VERSION 5.7 ;
BUSBITCHARS "[]" ;
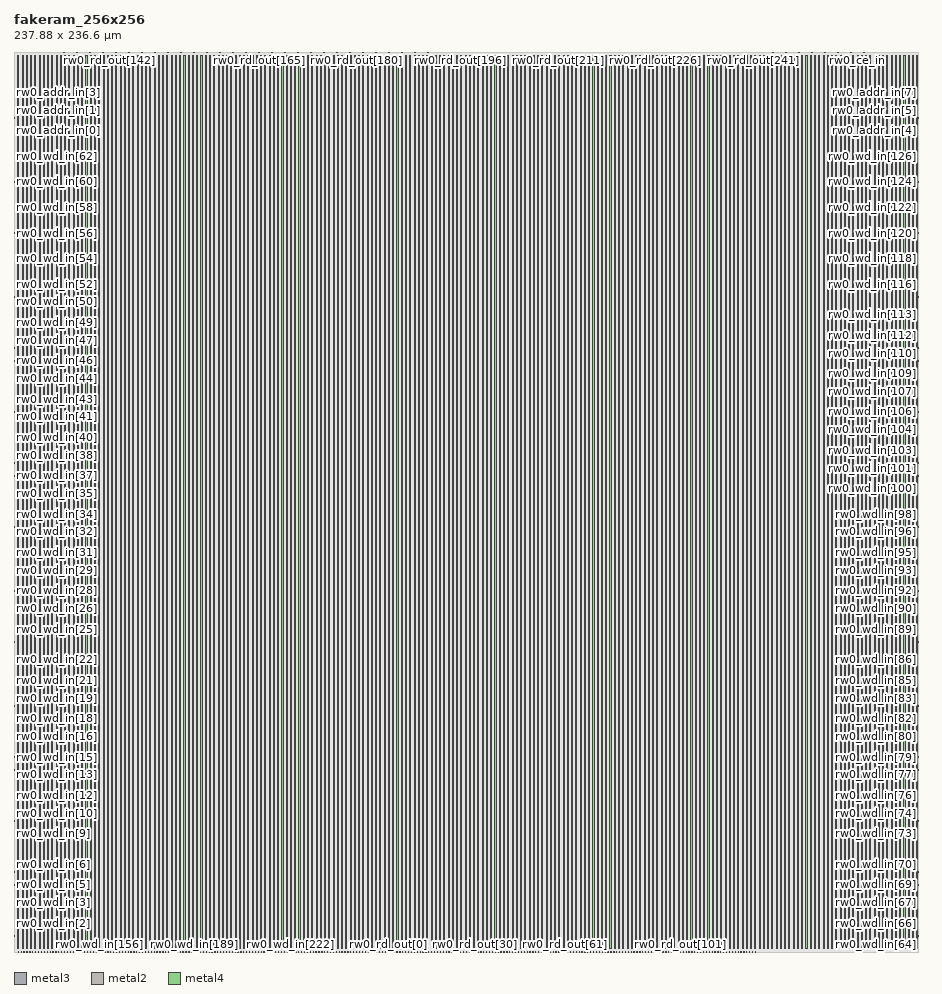
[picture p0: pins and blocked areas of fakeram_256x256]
MACRO fakeram_256x256
  FOREIGN fakeram_256x256 0 0 ;
  SYMMETRY X Y R90 ;
  SIZE 237.880 BY 236.600 ;
  CLASS BLOCK ;
  PIN rw0_wd_in[0]
    DIRECTION INPUT ;
    USE SIGNAL ;
    SHAPE ABUTMENT ;
    PORT
      LAYER metal3 ;
      RECT 0.000 0.805 0.210 0.875 ;
    END
  END rw0_wd_in[0]
  PIN rw0_wd_in[1]
    DIRECTION INPUT ;
    USE SIGNAL ;
    SHAPE ABUTMENT ;
    PORT
      LAYER metal3 ;
      RECT 0.000 4.165 0.210 4.235 ;
    END
  END rw0_wd_in[1]
  PIN rw0_wd_in[2]
    DIRECTION INPUT ;
    USE SIGNAL ;
    SHAPE ABUTMENT ;
    PORT
      LAYER metal3 ;
      RECT 0.000 7.525 0.210 7.595 ;
    END
  END rw0_wd_in[2]
  PIN rw0_wd_in[3]
    DIRECTION INPUT ;
    USE SIGNAL ;
    SHAPE ABUTMENT ;
    PORT
      LAYER metal3 ;
      RECT 0.000 10.885 0.210 10.955 ;
    END
  END rw0_wd_in[3]
  PIN rw0_wd_in[4]
    DIRECTION INPUT ;
    USE SIGNAL ;
    SHAPE ABUTMENT ;
    PORT
      LAYER metal3 ;
      RECT 0.000 14.245 0.210 14.315 ;
    END
  END rw0_wd_in[4]
  PIN rw0_wd_in[5]
    DIRECTION INPUT ;
    USE SIGNAL ;
    SHAPE ABUTMENT ;
    PORT
      LAYER metal3 ;
      RECT 0.000 17.605 0.210 17.675 ;
    END
  END rw0_wd_in[5]
  PIN rw0_wd_in[6]
    DIRECTION INPUT ;
    USE SIGNAL ;
    SHAPE ABUTMENT ;
    PORT
      LAYER metal3 ;
      RECT 0.000 20.965 0.210 21.035 ;
    END
  END rw0_wd_in[6]
  PIN rw0_wd_in[7]
    DIRECTION INPUT ;
    USE SIGNAL ;
    SHAPE ABUTMENT ;
    PORT
      LAYER metal3 ;
      RECT 0.000 24.325 0.210 24.395 ;
    END
  END rw0_wd_in[7]
  PIN rw0_wd_in[8]
    DIRECTION INPUT ;
    USE SIGNAL ;
    SHAPE ABUTMENT ;
    PORT
      LAYER metal3 ;
      RECT 0.000 27.685 0.210 27.755 ;
    END
  END rw0_wd_in[8]
  PIN rw0_wd_in[9]
    DIRECTION INPUT ;
    USE SIGNAL ;
    SHAPE ABUTMENT ;
    PORT
      LAYER metal3 ;
      RECT 0.000 31.045 0.210 31.115 ;
    END
  END rw0_wd_in[9]
  PIN rw0_wd_in[10]
    DIRECTION INPUT ;
    USE SIGNAL ;
    SHAPE ABUTMENT ;
    PORT
      LAYER metal3 ;
      RECT 0.000 34.405 0.210 34.475 ;
    END
  END rw0_wd_in[10]
  PIN rw0_wd_in[11]
    DIRECTION INPUT ;
    USE SIGNAL ;
    SHAPE ABUTMENT ;
    PORT
      LAYER metal3 ;
      RECT 0.000 37.765 0.210 37.835 ;
    END
  END rw0_wd_in[11]
  PIN rw0_wd_in[12]
    DIRECTION INPUT ;
    USE SIGNAL ;
    SHAPE ABUTMENT ;
    PORT
      LAYER metal3 ;
      RECT 0.000 41.125 0.210 41.195 ;
    END
  END rw0_wd_in[12]
  PIN rw0_wd_in[13]
    DIRECTION INPUT ;
    USE SIGNAL ;
    SHAPE ABUTMENT ;
    PORT
      LAYER metal3 ;
      RECT 0.000 44.485 0.210 44.555 ;
    END
  END rw0_wd_in[13]
  PIN rw0_wd_in[14]
    DIRECTION INPUT ;
    USE SIGNAL ;
    SHAPE ABUTMENT ;
    PORT
      LAYER metal3 ;
      RECT 0.000 47.845 0.210 47.915 ;
    END
  END rw0_wd_in[14]
  PIN rw0_wd_in[15]
    DIRECTION INPUT ;
    USE SIGNAL ;
    SHAPE ABUTMENT ;
    PORT
      LAYER metal3 ;
      RECT 0.000 51.205 0.210 51.275 ;
    END
  END rw0_wd_in[15]
  PIN rw0_wd_in[16]
    DIRECTION INPUT ;
    USE SIGNAL ;
    SHAPE ABUTMENT ;
    PORT
      LAYER metal3 ;
      RECT 0.000 54.565 0.210 54.635 ;
    END
  END rw0_wd_in[16]
  PIN rw0_wd_in[17]
    DIRECTION INPUT ;
    USE SIGNAL ;
    SHAPE ABUTMENT ;
    PORT
      LAYER metal3 ;
      RECT 0.000 57.925 0.210 57.995 ;
    END
  END rw0_wd_in[17]
  PIN rw0_wd_in[18]
    DIRECTION INPUT ;
    USE SIGNAL ;
    SHAPE ABUTMENT ;
    PORT
      LAYER metal3 ;
      RECT 0.000 61.285 0.210 61.355 ;
    END
  END rw0_wd_in[18]
  PIN rw0_wd_in[19]
    DIRECTION INPUT ;
    USE SIGNAL ;
    SHAPE ABUTMENT ;
    PORT
      LAYER metal3 ;
      RECT 0.000 64.645 0.210 64.715 ;
    END
  END rw0_wd_in[19]
  PIN rw0_wd_in[20]
    DIRECTION INPUT ;
    USE SIGNAL ;
    SHAPE ABUTMENT ;
    PORT
      LAYER metal3 ;
      RECT 0.000 68.005 0.210 68.075 ;
    END
  END rw0_wd_in[20]
  PIN rw0_wd_in[21]
    DIRECTION INPUT ;
    USE SIGNAL ;
    SHAPE ABUTMENT ;
    PORT
      LAYER metal3 ;
      RECT 0.000 71.365 0.210 71.435 ;
    END
  END rw0_wd_in[21]
  PIN rw0_wd_in[22]
    DIRECTION INPUT ;
    USE SIGNAL ;
    SHAPE ABUTMENT ;
    PORT
      LAYER metal3 ;
      RECT 0.000 74.725 0.210 74.795 ;
    END
  END rw0_wd_in[22]
  PIN rw0_wd_in[23]
    DIRECTION INPUT ;
    USE SIGNAL ;
    SHAPE ABUTMENT ;
    PORT
      LAYER metal3 ;
      RECT 0.000 78.085 0.210 78.155 ;
    END
  END rw0_wd_in[23]
  PIN rw0_wd_in[24]
    DIRECTION INPUT ;
    USE SIGNAL ;
    SHAPE ABUTMENT ;
    PORT
      LAYER metal3 ;
      RECT 0.000 81.445 0.210 81.515 ;
    END
  END rw0_wd_in[24]
  PIN rw0_wd_in[25]
    DIRECTION INPUT ;
    USE SIGNAL ;
    SHAPE ABUTMENT ;
    PORT
      LAYER metal3 ;
      RECT 0.000 84.805 0.210 84.875 ;
    END
  END rw0_wd_in[25]
  PIN rw0_wd_in[26]
    DIRECTION INPUT ;
    USE SIGNAL ;
    SHAPE ABUTMENT ;
    PORT
      LAYER metal3 ;
      RECT 0.000 88.165 0.210 88.235 ;
    END
  END rw0_wd_in[26]
  PIN rw0_wd_in[27]
    DIRECTION INPUT ;
    USE SIGNAL ;
    SHAPE ABUTMENT ;
    PORT
      LAYER metal3 ;
      RECT 0.000 91.525 0.210 91.595 ;
    END
  END rw0_wd_in[27]
  PIN rw0_wd_in[28]
    DIRECTION INPUT ;
    USE SIGNAL ;
    SHAPE ABUTMENT ;
    PORT
      LAYER metal3 ;
      RECT 0.000 94.885 0.210 94.955 ;
    END
  END rw0_wd_in[28]
  PIN rw0_wd_in[29]
    DIRECTION INPUT ;
    USE SIGNAL ;
    SHAPE ABUTMENT ;
    PORT
      LAYER metal3 ;
      RECT 0.000 98.245 0.210 98.315 ;
    END
  END rw0_wd_in[29]
  PIN rw0_wd_in[30]
    DIRECTION INPUT ;
    USE SIGNAL ;
    SHAPE ABUTMENT ;
    PORT
      LAYER metal3 ;
      RECT 0.000 101.605 0.210 101.675 ;
    END
  END rw0_wd_in[30]
  PIN rw0_wd_in[31]
    DIRECTION INPUT ;
    USE SIGNAL ;
    SHAPE ABUTMENT ;
    PORT
      LAYER metal3 ;
      RECT 0.000 104.965 0.210 105.035 ;
    END
  END rw0_wd_in[31]
  PIN rw0_wd_in[32]
    DIRECTION INPUT ;
    USE SIGNAL ;
    SHAPE ABUTMENT ;
    PORT
      LAYER metal3 ;
      RECT 0.000 108.325 0.210 108.395 ;
    END
  END rw0_wd_in[32]
  PIN rw0_wd_in[33]
    DIRECTION INPUT ;
    USE SIGNAL ;
    SHAPE ABUTMENT ;
    PORT
      LAYER metal3 ;
      RECT 0.000 111.685 0.210 111.755 ;
    END
  END rw0_wd_in[33]
  PIN rw0_wd_in[34]
    DIRECTION INPUT ;
    USE SIGNAL ;
    SHAPE ABUTMENT ;
    PORT
      LAYER metal3 ;
      RECT 0.000 115.045 0.210 115.115 ;
    END
  END rw0_wd_in[34]
  PIN rw0_wd_in[35]
    DIRECTION INPUT ;
    USE SIGNAL ;
    SHAPE ABUTMENT ;
    PORT
      LAYER metal3 ;
      RECT 0.000 118.405 0.210 118.475 ;
    END
  END rw0_wd_in[35]
  PIN rw0_wd_in[36]
    DIRECTION INPUT ;
    USE SIGNAL ;
    SHAPE ABUTMENT ;
    PORT
      LAYER metal3 ;
      RECT 0.000 121.765 0.210 121.835 ;
    END
  END rw0_wd_in[36]
  PIN rw0_wd_in[37]
    DIRECTION INPUT ;
    USE SIGNAL ;
    SHAPE ABUTMENT ;
    PORT
      LAYER metal3 ;
      RECT 0.000 125.125 0.210 125.195 ;
    END
  END rw0_wd_in[37]
  PIN rw0_wd_in[38]
    DIRECTION INPUT ;
    USE SIGNAL ;
    SHAPE ABUTMENT ;
    PORT
      LAYER metal3 ;
      RECT 0.000 128.485 0.210 128.555 ;
    END
  END rw0_wd_in[38]
  PIN rw0_wd_in[39]
    DIRECTION INPUT ;
    USE SIGNAL ;
    SHAPE ABUTMENT ;
    PORT
      LAYER metal3 ;
      RECT 0.000 131.845 0.210 131.915 ;
    END
  END rw0_wd_in[39]
  PIN rw0_wd_in[40]
    DIRECTION INPUT ;
    USE SIGNAL ;
    SHAPE ABUTMENT ;
    PORT
      LAYER metal3 ;
      RECT 0.000 135.205 0.210 135.275 ;
    END
  END rw0_wd_in[40]
  PIN rw0_wd_in[41]
    DIRECTION INPUT ;
    USE SIGNAL ;
    SHAPE ABUTMENT ;
    PORT
      LAYER metal3 ;
      RECT 0.000 138.565 0.210 138.635 ;
    END
  END rw0_wd_in[41]
  PIN rw0_wd_in[42]
    DIRECTION INPUT ;
    USE SIGNAL ;
    SHAPE ABUTMENT ;
    PORT
      LAYER metal3 ;
      RECT 0.000 141.925 0.210 141.995 ;
    END
  END rw0_wd_in[42]
  PIN rw0_wd_in[43]
    DIRECTION INPUT ;
    USE SIGNAL ;
    SHAPE ABUTMENT ;
    PORT
      LAYER metal3 ;
      RECT 0.000 145.285 0.210 145.355 ;
    END
  END rw0_wd_in[43]
  PIN rw0_wd_in[44]
    DIRECTION INPUT ;
    USE SIGNAL ;
    SHAPE ABUTMENT ;
    PORT
      LAYER metal3 ;
      RECT 0.000 148.645 0.210 148.715 ;
    END
  END rw0_wd_in[44]
  PIN rw0_wd_in[45]
    DIRECTION INPUT ;
    USE SIGNAL ;
    SHAPE ABUTMENT ;
    PORT
      LAYER metal3 ;
      RECT 0.000 152.005 0.210 152.075 ;
    END
  END rw0_wd_in[45]
  PIN rw0_wd_in[46]
    DIRECTION INPUT ;
    USE SIGNAL ;
    SHAPE ABUTMENT ;
    PORT
      LAYER metal3 ;
      RECT 0.000 155.365 0.210 155.435 ;
    END
  END rw0_wd_in[46]
  PIN rw0_wd_in[47]
    DIRECTION INPUT ;
    USE SIGNAL ;
    SHAPE ABUTMENT ;
    PORT
      LAYER metal3 ;
      RECT 0.000 158.725 0.210 158.795 ;
    END
  END rw0_wd_in[47]
  PIN rw0_wd_in[48]
    DIRECTION INPUT ;
    USE SIGNAL ;
    SHAPE ABUTMENT ;
    PORT
      LAYER metal3 ;
      RECT 0.000 162.085 0.210 162.155 ;
    END
  END rw0_wd_in[48]
  PIN rw0_wd_in[49]
    DIRECTION INPUT ;
    USE SIGNAL ;
    SHAPE ABUTMENT ;
    PORT
      LAYER metal3 ;
      RECT 0.000 165.445 0.210 165.515 ;
    END
  END rw0_wd_in[49]
  PIN rw0_wd_in[50]
    DIRECTION INPUT ;
    USE SIGNAL ;
    SHAPE ABUTMENT ;
    PORT
      LAYER metal3 ;
      RECT 0.000 168.805 0.210 168.875 ;
    END
  END rw0_wd_in[50]
  PIN rw0_wd_in[51]
    DIRECTION INPUT ;
    USE SIGNAL ;
    SHAPE ABUTMENT ;
    PORT
      LAYER metal3 ;
      RECT 0.000 172.165 0.210 172.235 ;
    END
  END rw0_wd_in[51]
  PIN rw0_wd_in[52]
    DIRECTION INPUT ;
    USE SIGNAL ;
    SHAPE ABUTMENT ;
    PORT
      LAYER metal3 ;
      RECT 0.000 175.525 0.210 175.595 ;
    END
  END rw0_wd_in[52]
  PIN rw0_wd_in[53]
    DIRECTION INPUT ;
    USE SIGNAL ;
    SHAPE ABUTMENT ;
    PORT
      LAYER metal3 ;
      RECT 0.000 178.885 0.210 178.955 ;
    END
  END rw0_wd_in[53]
  PIN rw0_wd_in[54]
    DIRECTION INPUT ;
    USE SIGNAL ;
    SHAPE ABUTMENT ;
    PORT
      LAYER metal3 ;
      RECT 0.000 182.245 0.210 182.315 ;
    END
  END rw0_wd_in[54]
  PIN rw0_wd_in[55]
    DIRECTION INPUT ;
    USE SIGNAL ;
    SHAPE ABUTMENT ;
    PORT
      LAYER metal3 ;
      RECT 0.000 185.605 0.210 185.675 ;
    END
  END rw0_wd_in[55]
  PIN rw0_wd_in[56]
    DIRECTION INPUT ;
    USE SIGNAL ;
    SHAPE ABUTMENT ;
    PORT
      LAYER metal3 ;
      RECT 0.000 188.965 0.210 189.035 ;
    END
  END rw0_wd_in[56]
  PIN rw0_wd_in[57]
    DIRECTION INPUT ;
    USE SIGNAL ;
    SHAPE ABUTMENT ;
    PORT
      LAYER metal3 ;
      RECT 0.000 192.325 0.210 192.395 ;
    END
  END rw0_wd_in[57]
  PIN rw0_wd_in[58]
    DIRECTION INPUT ;
    USE SIGNAL ;
    SHAPE ABUTMENT ;
    PORT
      LAYER metal3 ;
      RECT 0.000 195.685 0.210 195.755 ;
    END
  END rw0_wd_in[58]
  PIN rw0_wd_in[59]
    DIRECTION INPUT ;
    USE SIGNAL ;
    SHAPE ABUTMENT ;
    PORT
      LAYER metal3 ;
      RECT 0.000 199.045 0.210 199.115 ;
    END
  END rw0_wd_in[59]
  PIN rw0_wd_in[60]
    DIRECTION INPUT ;
    USE SIGNAL ;
    SHAPE ABUTMENT ;
    PORT
      LAYER metal3 ;
      RECT 0.000 202.405 0.210 202.475 ;
    END
  END rw0_wd_in[60]
  PIN rw0_wd_in[61]
    DIRECTION INPUT ;
    USE SIGNAL ;
    SHAPE ABUTMENT ;
    PORT
      LAYER metal3 ;
      RECT 0.000 205.765 0.210 205.835 ;
    END
  END rw0_wd_in[61]
  PIN rw0_wd_in[62]
    DIRECTION INPUT ;
    USE SIGNAL ;
    SHAPE ABUTMENT ;
    PORT
      LAYER metal3 ;
      RECT 0.000 209.125 0.210 209.195 ;
    END
  END rw0_wd_in[62]
  PIN rw0_wd_in[63]
    DIRECTION INPUT ;
    USE SIGNAL ;
    SHAPE ABUTMENT ;
    PORT
      LAYER metal3 ;
      RECT 0.000 212.485 0.210 212.555 ;
    END
  END rw0_wd_in[63]
  PIN rw0_wd_in[64]
    DIRECTION INPUT ;
    USE SIGNAL ;
    SHAPE ABUTMENT ;
    PORT
      LAYER metal3 ;
      RECT 237.670 0.805 237.880 0.875 ;
    END
  END rw0_wd_in[64]
  PIN rw0_wd_in[65]
    DIRECTION INPUT ;
    USE SIGNAL ;
    SHAPE ABUTMENT ;
    PORT
      LAYER metal3 ;
      RECT 237.670 4.165 237.880 4.235 ;
    END
  END rw0_wd_in[65]
  PIN rw0_wd_in[66]
    DIRECTION INPUT ;
    USE SIGNAL ;
    SHAPE ABUTMENT ;
    PORT
      LAYER metal3 ;
      RECT 237.670 7.525 237.880 7.595 ;
    END
  END rw0_wd_in[66]
  PIN rw0_wd_in[67]
    DIRECTION INPUT ;
    USE SIGNAL ;
    SHAPE ABUTMENT ;
    PORT
      LAYER metal3 ;
      RECT 237.670 10.885 237.880 10.955 ;
    END
  END rw0_wd_in[67]
  PIN rw0_wd_in[68]
    DIRECTION INPUT ;
    USE SIGNAL ;
    SHAPE ABUTMENT ;
    PORT
      LAYER metal3 ;
      RECT 237.670 14.245 237.880 14.315 ;
    END
  END rw0_wd_in[68]
  PIN rw0_wd_in[69]
    DIRECTION INPUT ;
    USE SIGNAL ;
    SHAPE ABUTMENT ;
    PORT
      LAYER metal3 ;
      RECT 237.670 17.605 237.880 17.675 ;
    END
  END rw0_wd_in[69]
  PIN rw0_wd_in[70]
    DIRECTION INPUT ;
    USE SIGNAL ;
    SHAPE ABUTMENT ;
    PORT
      LAYER metal3 ;
      RECT 237.670 20.965 237.880 21.035 ;
    END
  END rw0_wd_in[70]
  PIN rw0_wd_in[71]
    DIRECTION INPUT ;
    USE SIGNAL ;
    SHAPE ABUTMENT ;
    PORT
      LAYER metal3 ;
      RECT 237.670 24.325 237.880 24.395 ;
    END
  END rw0_wd_in[71]
  PIN rw0_wd_in[72]
    DIRECTION INPUT ;
    USE SIGNAL ;
    SHAPE ABUTMENT ;
    PORT
      LAYER metal3 ;
      RECT 237.670 27.685 237.880 27.755 ;
    END
  END rw0_wd_in[72]
  PIN rw0_wd_in[73]
    DIRECTION INPUT ;
    USE SIGNAL ;
    SHAPE ABUTMENT ;
    PORT
      LAYER metal3 ;
      RECT 237.670 31.045 237.880 31.115 ;
    END
  END rw0_wd_in[73]
  PIN rw0_wd_in[74]
    DIRECTION INPUT ;
    USE SIGNAL ;
    SHAPE ABUTMENT ;
    PORT
      LAYER metal3 ;
      RECT 237.670 34.405 237.880 34.475 ;
    END
  END rw0_wd_in[74]
  PIN rw0_wd_in[75]
    DIRECTION INPUT ;
    USE SIGNAL ;
    SHAPE ABUTMENT ;
    PORT
      LAYER metal3 ;
      RECT 237.670 37.765 237.880 37.835 ;
    END
  END rw0_wd_in[75]
  PIN rw0_wd_in[76]
    DIRECTION INPUT ;
    USE SIGNAL ;
    SHAPE ABUTMENT ;
    PORT
      LAYER metal3 ;
      RECT 237.670 41.125 237.880 41.195 ;
    END
  END rw0_wd_in[76]
  PIN rw0_wd_in[77]
    DIRECTION INPUT ;
    USE SIGNAL ;
    SHAPE ABUTMENT ;
    PORT
      LAYER metal3 ;
      RECT 237.670 44.485 237.880 44.555 ;
    END
  END rw0_wd_in[77]
  PIN rw0_wd_in[78]
    DIRECTION INPUT ;
    USE SIGNAL ;
    SHAPE ABUTMENT ;
    PORT
      LAYER metal3 ;
      RECT 237.670 47.845 237.880 47.915 ;
    END
  END rw0_wd_in[78]
  PIN rw0_wd_in[79]
    DIRECTION INPUT ;
    USE SIGNAL ;
    SHAPE ABUTMENT ;
    PORT
      LAYER metal3 ;
      RECT 237.670 51.205 237.880 51.275 ;
    END
  END rw0_wd_in[79]
  PIN rw0_wd_in[80]
    DIRECTION INPUT ;
    USE SIGNAL ;
    SHAPE ABUTMENT ;
    PORT
      LAYER metal3 ;
      RECT 237.670 54.565 237.880 54.635 ;
    END
  END rw0_wd_in[80]
  PIN rw0_wd_in[81]
    DIRECTION INPUT ;
    USE SIGNAL ;
    SHAPE ABUTMENT ;
    PORT
      LAYER metal3 ;
      RECT 237.670 57.925 237.880 57.995 ;
    END
  END rw0_wd_in[81]
  PIN rw0_wd_in[82]
    DIRECTION INPUT ;
    USE SIGNAL ;
    SHAPE ABUTMENT ;
    PORT
      LAYER metal3 ;
      RECT 237.670 61.285 237.880 61.355 ;
    END
  END rw0_wd_in[82]
  PIN rw0_wd_in[83]
    DIRECTION INPUT ;
    USE SIGNAL ;
    SHAPE ABUTMENT ;
    PORT
      LAYER metal3 ;
      RECT 237.670 64.645 237.880 64.715 ;
    END
  END rw0_wd_in[83]
  PIN rw0_wd_in[84]
    DIRECTION INPUT ;
    USE SIGNAL ;
    SHAPE ABUTMENT ;
    PORT
      LAYER metal3 ;
      RECT 237.670 68.005 237.880 68.075 ;
    END
  END rw0_wd_in[84]
  PIN rw0_wd_in[85]
    DIRECTION INPUT ;
    USE SIGNAL ;
    SHAPE ABUTMENT ;
    PORT
      LAYER metal3 ;
      RECT 237.670 71.365 237.880 71.435 ;
    END
  END rw0_wd_in[85]
  PIN rw0_wd_in[86]
    DIRECTION INPUT ;
    USE SIGNAL ;
    SHAPE ABUTMENT ;
    PORT
      LAYER metal3 ;
      RECT 237.670 74.725 237.880 74.795 ;
    END
  END rw0_wd_in[86]
  PIN rw0_wd_in[87]
    DIRECTION INPUT ;
    USE SIGNAL ;
    SHAPE ABUTMENT ;
    PORT
      LAYER metal3 ;
      RECT 237.670 78.085 237.880 78.155 ;
    END
  END rw0_wd_in[87]
  PIN rw0_wd_in[88]
    DIRECTION INPUT ;
    USE SIGNAL ;
    SHAPE ABUTMENT ;
    PORT
      LAYER metal3 ;
      RECT 237.670 81.445 237.880 81.515 ;
    END
  END rw0_wd_in[88]
  PIN rw0_wd_in[89]
    DIRECTION INPUT ;
    USE SIGNAL ;
    SHAPE ABUTMENT ;
    PORT
      LAYER metal3 ;
      RECT 237.670 84.805 237.880 84.875 ;
    END
  END rw0_wd_in[89]
  PIN rw0_wd_in[90]
    DIRECTION INPUT ;
    USE SIGNAL ;
    SHAPE ABUTMENT ;
    PORT
      LAYER metal3 ;
      RECT 237.670 88.165 237.880 88.235 ;
    END
  END rw0_wd_in[90]
  PIN rw0_wd_in[91]
    DIRECTION INPUT ;
    USE SIGNAL ;
    SHAPE ABUTMENT ;
    PORT
      LAYER metal3 ;
      RECT 237.670 91.525 237.880 91.595 ;
    END
  END rw0_wd_in[91]
  PIN rw0_wd_in[92]
    DIRECTION INPUT ;
    USE SIGNAL ;
    SHAPE ABUTMENT ;
    PORT
      LAYER metal3 ;
      RECT 237.670 94.885 237.880 94.955 ;
    END
  END rw0_wd_in[92]
  PIN rw0_wd_in[93]
    DIRECTION INPUT ;
    USE SIGNAL ;
    SHAPE ABUTMENT ;
    PORT
      LAYER metal3 ;
      RECT 237.670 98.245 237.880 98.315 ;
    END
  END rw0_wd_in[93]
  PIN rw0_wd_in[94]
    DIRECTION INPUT ;
    USE SIGNAL ;
    SHAPE ABUTMENT ;
    PORT
      LAYER metal3 ;
      RECT 237.670 101.605 237.880 101.675 ;
    END
  END rw0_wd_in[94]
  PIN rw0_wd_in[95]
    DIRECTION INPUT ;
    USE SIGNAL ;
    SHAPE ABUTMENT ;
    PORT
      LAYER metal3 ;
      RECT 237.670 104.965 237.880 105.035 ;
    END
  END rw0_wd_in[95]
  PIN rw0_wd_in[96]
    DIRECTION INPUT ;
    USE SIGNAL ;
    SHAPE ABUTMENT ;
    PORT
      LAYER metal3 ;
      RECT 237.670 108.325 237.880 108.395 ;
    END
  END rw0_wd_in[96]
  PIN rw0_wd_in[97]
    DIRECTION INPUT ;
    USE SIGNAL ;
    SHAPE ABUTMENT ;
    PORT
      LAYER metal3 ;
      RECT 237.670 111.685 237.880 111.755 ;
    END
  END rw0_wd_in[97]
  PIN rw0_wd_in[98]
    DIRECTION INPUT ;
    USE SIGNAL ;
    SHAPE ABUTMENT ;
    PORT
      LAYER metal3 ;
      RECT 237.670 115.045 237.880 115.115 ;
    END
  END rw0_wd_in[98]
  PIN rw0_wd_in[99]
    DIRECTION INPUT ;
    USE SIGNAL ;
    SHAPE ABUTMENT ;
    PORT
      LAYER metal3 ;
      RECT 237.670 118.405 237.880 118.475 ;
    END
  END rw0_wd_in[99]
  PIN rw0_wd_in[100]
    DIRECTION INPUT ;
    USE SIGNAL ;
    SHAPE ABUTMENT ;
    PORT
      LAYER metal3 ;
      RECT 237.670 121.765 237.880 121.835 ;
    END
  END rw0_wd_in[100]
  PIN rw0_wd_in[101]
    DIRECTION INPUT ;
    USE SIGNAL ;
    SHAPE ABUTMENT ;
    PORT
      LAYER metal3 ;
      RECT 237.670 125.125 237.880 125.195 ;
    END
  END rw0_wd_in[101]
  PIN rw0_wd_in[102]
    DIRECTION INPUT ;
    USE SIGNAL ;
    SHAPE ABUTMENT ;
    PORT
      LAYER metal3 ;
      RECT 237.670 128.485 237.880 128.555 ;
    END
  END rw0_wd_in[102]
  PIN rw0_wd_in[103]
    DIRECTION INPUT ;
    USE SIGNAL ;
    SHAPE ABUTMENT ;
    PORT
      LAYER metal3 ;
      RECT 237.670 131.845 237.880 131.915 ;
    END
  END rw0_wd_in[103]
  PIN rw0_wd_in[104]
    DIRECTION INPUT ;
    USE SIGNAL ;
    SHAPE ABUTMENT ;
    PORT
      LAYER metal3 ;
      RECT 237.670 135.205 237.880 135.275 ;
    END
  END rw0_wd_in[104]
  PIN rw0_wd_in[105]
    DIRECTION INPUT ;
    USE SIGNAL ;
    SHAPE ABUTMENT ;
    PORT
      LAYER metal3 ;
      RECT 237.670 138.565 237.880 138.635 ;
    END
  END rw0_wd_in[105]
  PIN rw0_wd_in[106]
    DIRECTION INPUT ;
    USE SIGNAL ;
    SHAPE ABUTMENT ;
    PORT
      LAYER metal3 ;
      RECT 237.670 141.925 237.880 141.995 ;
    END
  END rw0_wd_in[106]
  PIN rw0_wd_in[107]
    DIRECTION INPUT ;
    USE SIGNAL ;
    SHAPE ABUTMENT ;
    PORT
      LAYER metal3 ;
      RECT 237.670 145.285 237.880 145.355 ;
    END
  END rw0_wd_in[107]
  PIN rw0_wd_in[108]
    DIRECTION INPUT ;
    USE SIGNAL ;
    SHAPE ABUTMENT ;
    PORT
      LAYER metal3 ;
      RECT 237.670 148.645 237.880 148.715 ;
    END
  END rw0_wd_in[108]
  PIN rw0_wd_in[109]
    DIRECTION INPUT ;
    USE SIGNAL ;
    SHAPE ABUTMENT ;
    PORT
      LAYER metal3 ;
      RECT 237.670 152.005 237.880 152.075 ;
    END
  END rw0_wd_in[109]
  PIN rw0_wd_in[110]
    DIRECTION INPUT ;
    USE SIGNAL ;
    SHAPE ABUTMENT ;
    PORT
      LAYER metal3 ;
      RECT 237.670 155.365 237.880 155.435 ;
    END
  END rw0_wd_in[110]
  PIN rw0_wd_in[111]
    DIRECTION INPUT ;
    USE SIGNAL ;
    SHAPE ABUTMENT ;
    PORT
      LAYER metal3 ;
      RECT 237.670 158.725 237.880 158.795 ;
    END
  END rw0_wd_in[111]
  PIN rw0_wd_in[112]
    DIRECTION INPUT ;
    USE SIGNAL ;
    SHAPE ABUTMENT ;
    PORT
      LAYER metal3 ;
      RECT 237.670 162.085 237.880 162.155 ;
    END
  END rw0_wd_in[112]
  PIN rw0_wd_in[113]
    DIRECTION INPUT ;
    USE SIGNAL ;
    SHAPE ABUTMENT ;
    PORT
      LAYER metal3 ;
      RECT 237.670 165.445 237.880 165.515 ;
    END
  END rw0_wd_in[113]
  PIN rw0_wd_in[114]
    DIRECTION INPUT ;
    USE SIGNAL ;
    SHAPE ABUTMENT ;
    PORT
      LAYER metal3 ;
      RECT 237.670 168.805 237.880 168.875 ;
    END
  END rw0_wd_in[114]
  PIN rw0_wd_in[115]
    DIRECTION INPUT ;
    USE SIGNAL ;
    SHAPE ABUTMENT ;
    PORT
      LAYER metal3 ;
      RECT 237.670 172.165 237.880 172.235 ;
    END
  END rw0_wd_in[115]
  PIN rw0_wd_in[116]
    DIRECTION INPUT ;
    USE SIGNAL ;
    SHAPE ABUTMENT ;
    PORT
      LAYER metal3 ;
      RECT 237.670 175.525 237.880 175.595 ;
    END
  END rw0_wd_in[116]
  PIN rw0_wd_in[117]
    DIRECTION INPUT ;
    USE SIGNAL ;
    SHAPE ABUTMENT ;
    PORT
      LAYER metal3 ;
      RECT 237.670 178.885 237.880 178.955 ;
    END
  END rw0_wd_in[117]
  PIN rw0_wd_in[118]
    DIRECTION INPUT ;
    USE SIGNAL ;
    SHAPE ABUTMENT ;
    PORT
      LAYER metal3 ;
      RECT 237.670 182.245 237.880 182.315 ;
    END
  END rw0_wd_in[118]
  PIN rw0_wd_in[119]
    DIRECTION INPUT ;
    USE SIGNAL ;
    SHAPE ABUTMENT ;
    PORT
      LAYER metal3 ;
      RECT 237.670 185.605 237.880 185.675 ;
    END
  END rw0_wd_in[119]
  PIN rw0_wd_in[120]
    DIRECTION INPUT ;
    USE SIGNAL ;
    SHAPE ABUTMENT ;
    PORT
      LAYER metal3 ;
      RECT 237.670 188.965 237.880 189.035 ;
    END
  END rw0_wd_in[120]
  PIN rw0_wd_in[121]
    DIRECTION INPUT ;
    USE SIGNAL ;
    SHAPE ABUTMENT ;
    PORT
      LAYER metal3 ;
      RECT 237.670 192.325 237.880 192.395 ;
    END
  END rw0_wd_in[121]
  PIN rw0_wd_in[122]
    DIRECTION INPUT ;
    USE SIGNAL ;
    SHAPE ABUTMENT ;
    PORT
      LAYER metal3 ;
      RECT 237.670 195.685 237.880 195.755 ;
    END
  END rw0_wd_in[122]
  PIN rw0_wd_in[123]
    DIRECTION INPUT ;
    USE SIGNAL ;
    SHAPE ABUTMENT ;
    PORT
      LAYER metal3 ;
      RECT 237.670 199.045 237.880 199.115 ;
    END
  END rw0_wd_in[123]
  PIN rw0_wd_in[124]
    DIRECTION INPUT ;
    USE SIGNAL ;
    SHAPE ABUTMENT ;
    PORT
      LAYER metal3 ;
      RECT 237.670 202.405 237.880 202.475 ;
    END
  END rw0_wd_in[124]
  PIN rw0_wd_in[125]
    DIRECTION INPUT ;
    USE SIGNAL ;
    SHAPE ABUTMENT ;
    PORT
      LAYER metal3 ;
      RECT 237.670 205.765 237.880 205.835 ;
    END
  END rw0_wd_in[125]
  PIN rw0_wd_in[126]
    DIRECTION INPUT ;
    USE SIGNAL ;
    SHAPE ABUTMENT ;
    PORT
      LAYER metal3 ;
      RECT 237.670 209.125 237.880 209.195 ;
    END
  END rw0_wd_in[126]
  PIN rw0_wd_in[127]
    DIRECTION INPUT ;
    USE SIGNAL ;
    SHAPE ABUTMENT ;
    PORT
      LAYER metal3 ;
      RECT 237.670 212.485 237.880 212.555 ;
    END
  END rw0_wd_in[127]
  PIN rw0_wd_in[128]
    DIRECTION INPUT ;
    USE SIGNAL ;
    SHAPE ABUTMENT ;
    PORT
      LAYER metal2 ;
      RECT 1.105 0.000 1.175 0.210 ;
    END
  END rw0_wd_in[128]
  PIN rw0_wd_in[129]
    DIRECTION INPUT ;
    USE SIGNAL ;
    SHAPE ABUTMENT ;
    PORT
      LAYER metal2 ;
      RECT 1.865 0.000 1.935 0.210 ;
    END
  END rw0_wd_in[129]
  PIN rw0_wd_in[130]
    DIRECTION INPUT ;
    USE SIGNAL ;
    SHAPE ABUTMENT ;
    PORT
      LAYER metal2 ;
      RECT 2.625 0.000 2.695 0.210 ;
    END
  END rw0_wd_in[130]
  PIN rw0_wd_in[131]
    DIRECTION INPUT ;
    USE SIGNAL ;
    SHAPE ABUTMENT ;
    PORT
      LAYER metal2 ;
      RECT 3.385 0.000 3.455 0.210 ;
    END
  END rw0_wd_in[131]
  PIN rw0_wd_in[132]
    DIRECTION INPUT ;
    USE SIGNAL ;
    SHAPE ABUTMENT ;
    PORT
      LAYER metal2 ;
      RECT 4.145 0.000 4.215 0.210 ;
    END
  END rw0_wd_in[132]
  PIN rw0_wd_in[133]
    DIRECTION INPUT ;
    USE SIGNAL ;
    SHAPE ABUTMENT ;
    PORT
      LAYER metal2 ;
      RECT 4.905 0.000 4.975 0.210 ;
    END
  END rw0_wd_in[133]
  PIN rw0_wd_in[134]
    DIRECTION INPUT ;
    USE SIGNAL ;
    SHAPE ABUTMENT ;
    PORT
      LAYER metal2 ;
      RECT 5.665 0.000 5.735 0.210 ;
    END
  END rw0_wd_in[134]
  PIN rw0_wd_in[135]
    DIRECTION INPUT ;
    USE SIGNAL ;
    SHAPE ABUTMENT ;
    PORT
      LAYER metal2 ;
      RECT 6.425 0.000 6.495 0.210 ;
    END
  END rw0_wd_in[135]
  PIN rw0_wd_in[136]
    DIRECTION INPUT ;
    USE SIGNAL ;
    SHAPE ABUTMENT ;
    PORT
      LAYER metal2 ;
      RECT 7.185 0.000 7.255 0.210 ;
    END
  END rw0_wd_in[136]
  PIN rw0_wd_in[137]
    DIRECTION INPUT ;
    USE SIGNAL ;
    SHAPE ABUTMENT ;
    PORT
      LAYER metal2 ;
      RECT 7.945 0.000 8.015 0.210 ;
    END
  END rw0_wd_in[137]
  PIN rw0_wd_in[138]
    DIRECTION INPUT ;
    USE SIGNAL ;
    SHAPE ABUTMENT ;
    PORT
      LAYER metal2 ;
      RECT 8.705 0.000 8.775 0.210 ;
    END
  END rw0_wd_in[138]
  PIN rw0_wd_in[139]
    DIRECTION INPUT ;
    USE SIGNAL ;
    SHAPE ABUTMENT ;
    PORT
      LAYER metal2 ;
      RECT 9.465 0.000 9.535 0.210 ;
    END
  END rw0_wd_in[139]
  PIN rw0_wd_in[140]
    DIRECTION INPUT ;
    USE SIGNAL ;
    SHAPE ABUTMENT ;
    PORT
      LAYER metal2 ;
      RECT 10.225 0.000 10.295 0.210 ;
    END
  END rw0_wd_in[140]
  PIN rw0_wd_in[141]
    DIRECTION INPUT ;
    USE SIGNAL ;
    SHAPE ABUTMENT ;
    PORT
      LAYER metal2 ;
      RECT 10.985 0.000 11.055 0.210 ;
    END
  END rw0_wd_in[141]
  PIN rw0_wd_in[142]
    DIRECTION INPUT ;
    USE SIGNAL ;
    SHAPE ABUTMENT ;
    PORT
      LAYER metal2 ;
      RECT 11.745 0.000 11.815 0.210 ;
    END
  END rw0_wd_in[142]
  PIN rw0_wd_in[143]
    DIRECTION INPUT ;
    USE SIGNAL ;
    SHAPE ABUTMENT ;
    PORT
      LAYER metal2 ;
      RECT 12.505 0.000 12.575 0.210 ;
    END
  END rw0_wd_in[143]
  PIN rw0_wd_in[144]
    DIRECTION INPUT ;
    USE SIGNAL ;
    SHAPE ABUTMENT ;
    PORT
      LAYER metal2 ;
      RECT 13.265 0.000 13.335 0.210 ;
    END
  END rw0_wd_in[144]
  PIN rw0_wd_in[145]
    DIRECTION INPUT ;
    USE SIGNAL ;
    SHAPE ABUTMENT ;
    PORT
      LAYER metal2 ;
      RECT 14.025 0.000 14.095 0.210 ;
    END
  END rw0_wd_in[145]
  PIN rw0_wd_in[146]
    DIRECTION INPUT ;
    USE SIGNAL ;
    SHAPE ABUTMENT ;
    PORT
      LAYER metal2 ;
      RECT 14.785 0.000 14.855 0.210 ;
    END
  END rw0_wd_in[146]
  PIN rw0_wd_in[147]
    DIRECTION INPUT ;
    USE SIGNAL ;
    SHAPE ABUTMENT ;
    PORT
      LAYER metal2 ;
      RECT 15.545 0.000 15.615 0.210 ;
    END
  END rw0_wd_in[147]
  PIN rw0_wd_in[148]
    DIRECTION INPUT ;
    USE SIGNAL ;
    SHAPE ABUTMENT ;
    PORT
      LAYER metal2 ;
      RECT 16.305 0.000 16.375 0.210 ;
    END
  END rw0_wd_in[148]
  PIN rw0_wd_in[149]
    DIRECTION INPUT ;
    USE SIGNAL ;
    SHAPE ABUTMENT ;
    PORT
      LAYER metal2 ;
      RECT 17.065 0.000 17.135 0.210 ;
    END
  END rw0_wd_in[149]
  PIN rw0_wd_in[150]
    DIRECTION INPUT ;
    USE SIGNAL ;
    SHAPE ABUTMENT ;
    PORT
      LAYER metal2 ;
      RECT 17.825 0.000 17.895 0.210 ;
    END
  END rw0_wd_in[150]
  PIN rw0_wd_in[151]
    DIRECTION INPUT ;
    USE SIGNAL ;
    SHAPE ABUTMENT ;
    PORT
      LAYER metal2 ;
      RECT 18.585 0.000 18.655 0.210 ;
    END
  END rw0_wd_in[151]
  PIN rw0_wd_in[152]
    DIRECTION INPUT ;
    USE SIGNAL ;
    SHAPE ABUTMENT ;
    PORT
      LAYER metal2 ;
      RECT 19.345 0.000 19.415 0.210 ;
    END
  END rw0_wd_in[152]
  PIN rw0_wd_in[153]
    DIRECTION INPUT ;
    USE SIGNAL ;
    SHAPE ABUTMENT ;
    PORT
      LAYER metal2 ;
      RECT 20.105 0.000 20.175 0.210 ;
    END
  END rw0_wd_in[153]
  PIN rw0_wd_in[154]
    DIRECTION INPUT ;
    USE SIGNAL ;
    SHAPE ABUTMENT ;
    PORT
      LAYER metal2 ;
      RECT 20.865 0.000 20.935 0.210 ;
    END
  END rw0_wd_in[154]
  PIN rw0_wd_in[155]
    DIRECTION INPUT ;
    USE SIGNAL ;
    SHAPE ABUTMENT ;
    PORT
      LAYER metal2 ;
      RECT 21.625 0.000 21.695 0.210 ;
    END
  END rw0_wd_in[155]
  PIN rw0_wd_in[156]
    DIRECTION INPUT ;
    USE SIGNAL ;
    SHAPE ABUTMENT ;
    PORT
      LAYER metal2 ;
      RECT 22.385 0.000 22.455 0.210 ;
    END
  END rw0_wd_in[156]
  PIN rw0_wd_in[157]
    DIRECTION INPUT ;
    USE SIGNAL ;
    SHAPE ABUTMENT ;
    PORT
      LAYER metal2 ;
      RECT 23.145 0.000 23.215 0.210 ;
    END
  END rw0_wd_in[157]
  PIN rw0_wd_in[158]
    DIRECTION INPUT ;
    USE SIGNAL ;
    SHAPE ABUTMENT ;
    PORT
      LAYER metal2 ;
      RECT 23.905 0.000 23.975 0.210 ;
    END
  END rw0_wd_in[158]
  PIN rw0_wd_in[159]
    DIRECTION INPUT ;
    USE SIGNAL ;
    SHAPE ABUTMENT ;
    PORT
      LAYER metal2 ;
      RECT 24.665 0.000 24.735 0.210 ;
    END
  END rw0_wd_in[159]
  PIN rw0_wd_in[160]
    DIRECTION INPUT ;
    USE SIGNAL ;
    SHAPE ABUTMENT ;
    PORT
      LAYER metal2 ;
      RECT 25.425 0.000 25.495 0.210 ;
    END
  END rw0_wd_in[160]
  PIN rw0_wd_in[161]
    DIRECTION INPUT ;
    USE SIGNAL ;
    SHAPE ABUTMENT ;
    PORT
      LAYER metal2 ;
      RECT 26.185 0.000 26.255 0.210 ;
    END
  END rw0_wd_in[161]
  PIN rw0_wd_in[162]
    DIRECTION INPUT ;
    USE SIGNAL ;
    SHAPE ABUTMENT ;
    PORT
      LAYER metal2 ;
      RECT 26.945 0.000 27.015 0.210 ;
    END
  END rw0_wd_in[162]
  PIN rw0_wd_in[163]
    DIRECTION INPUT ;
    USE SIGNAL ;
    SHAPE ABUTMENT ;
    PORT
      LAYER metal2 ;
      RECT 27.705 0.000 27.775 0.210 ;
    END
  END rw0_wd_in[163]
  PIN rw0_wd_in[164]
    DIRECTION INPUT ;
    USE SIGNAL ;
    SHAPE ABUTMENT ;
    PORT
      LAYER metal2 ;
      RECT 28.465 0.000 28.535 0.210 ;
    END
  END rw0_wd_in[164]
  PIN rw0_wd_in[165]
    DIRECTION INPUT ;
    USE SIGNAL ;
    SHAPE ABUTMENT ;
    PORT
      LAYER metal2 ;
      RECT 29.225 0.000 29.295 0.210 ;
    END
  END rw0_wd_in[165]
  PIN rw0_wd_in[166]
    DIRECTION INPUT ;
    USE SIGNAL ;
    SHAPE ABUTMENT ;
    PORT
      LAYER metal2 ;
      RECT 29.985 0.000 30.055 0.210 ;
    END
  END rw0_wd_in[166]
  PIN rw0_wd_in[167]
    DIRECTION INPUT ;
    USE SIGNAL ;
    SHAPE ABUTMENT ;
    PORT
      LAYER metal2 ;
      RECT 30.745 0.000 30.815 0.210 ;
    END
  END rw0_wd_in[167]
  PIN rw0_wd_in[168]
    DIRECTION INPUT ;
    USE SIGNAL ;
    SHAPE ABUTMENT ;
    PORT
      LAYER metal2 ;
      RECT 31.505 0.000 31.575 0.210 ;
    END
  END rw0_wd_in[168]
  PIN rw0_wd_in[169]
    DIRECTION INPUT ;
    USE SIGNAL ;
    SHAPE ABUTMENT ;
    PORT
      LAYER metal2 ;
      RECT 32.265 0.000 32.335 0.210 ;
    END
  END rw0_wd_in[169]
  PIN rw0_wd_in[170]
    DIRECTION INPUT ;
    USE SIGNAL ;
    SHAPE ABUTMENT ;
    PORT
      LAYER metal2 ;
      RECT 33.025 0.000 33.095 0.210 ;
    END
  END rw0_wd_in[170]
  PIN rw0_wd_in[171]
    DIRECTION INPUT ;
    USE SIGNAL ;
    SHAPE ABUTMENT ;
    PORT
      LAYER metal2 ;
      RECT 33.785 0.000 33.855 0.210 ;
    END
  END rw0_wd_in[171]
  PIN rw0_wd_in[172]
    DIRECTION INPUT ;
    USE SIGNAL ;
    SHAPE ABUTMENT ;
    PORT
      LAYER metal2 ;
      RECT 34.545 0.000 34.615 0.210 ;
    END
  END rw0_wd_in[172]
  PIN rw0_wd_in[173]
    DIRECTION INPUT ;
    USE SIGNAL ;
    SHAPE ABUTMENT ;
    PORT
      LAYER metal2 ;
      RECT 35.305 0.000 35.375 0.210 ;
    END
  END rw0_wd_in[173]
  PIN rw0_wd_in[174]
    DIRECTION INPUT ;
    USE SIGNAL ;
    SHAPE ABUTMENT ;
    PORT
      LAYER metal2 ;
      RECT 36.065 0.000 36.135 0.210 ;
    END
  END rw0_wd_in[174]
  PIN rw0_wd_in[175]
    DIRECTION INPUT ;
    USE SIGNAL ;
    SHAPE ABUTMENT ;
    PORT
      LAYER metal2 ;
      RECT 36.825 0.000 36.895 0.210 ;
    END
  END rw0_wd_in[175]
  PIN rw0_wd_in[176]
    DIRECTION INPUT ;
    USE SIGNAL ;
    SHAPE ABUTMENT ;
    PORT
      LAYER metal2 ;
      RECT 37.585 0.000 37.655 0.210 ;
    END
  END rw0_wd_in[176]
  PIN rw0_wd_in[177]
    DIRECTION INPUT ;
    USE SIGNAL ;
    SHAPE ABUTMENT ;
    PORT
      LAYER metal2 ;
      RECT 38.345 0.000 38.415 0.210 ;
    END
  END rw0_wd_in[177]
  PIN rw0_wd_in[178]
    DIRECTION INPUT ;
    USE SIGNAL ;
    SHAPE ABUTMENT ;
    PORT
      LAYER metal2 ;
      RECT 39.105 0.000 39.175 0.210 ;
    END
  END rw0_wd_in[178]
  PIN rw0_wd_in[179]
    DIRECTION INPUT ;
    USE SIGNAL ;
    SHAPE ABUTMENT ;
    PORT
      LAYER metal2 ;
      RECT 39.865 0.000 39.935 0.210 ;
    END
  END rw0_wd_in[179]
  PIN rw0_wd_in[180]
    DIRECTION INPUT ;
    USE SIGNAL ;
    SHAPE ABUTMENT ;
    PORT
      LAYER metal2 ;
      RECT 40.625 0.000 40.695 0.210 ;
    END
  END rw0_wd_in[180]
  PIN rw0_wd_in[181]
    DIRECTION INPUT ;
    USE SIGNAL ;
    SHAPE ABUTMENT ;
    PORT
      LAYER metal2 ;
      RECT 41.385 0.000 41.455 0.210 ;
    END
  END rw0_wd_in[181]
  PIN rw0_wd_in[182]
    DIRECTION INPUT ;
    USE SIGNAL ;
    SHAPE ABUTMENT ;
    PORT
      LAYER metal2 ;
      RECT 42.145 0.000 42.215 0.210 ;
    END
  END rw0_wd_in[182]
  PIN rw0_wd_in[183]
    DIRECTION INPUT ;
    USE SIGNAL ;
    SHAPE ABUTMENT ;
    PORT
      LAYER metal2 ;
      RECT 42.905 0.000 42.975 0.210 ;
    END
  END rw0_wd_in[183]
  PIN rw0_wd_in[184]
    DIRECTION INPUT ;
    USE SIGNAL ;
    SHAPE ABUTMENT ;
    PORT
      LAYER metal2 ;
      RECT 43.665 0.000 43.735 0.210 ;
    END
  END rw0_wd_in[184]
  PIN rw0_wd_in[185]
    DIRECTION INPUT ;
    USE SIGNAL ;
    SHAPE ABUTMENT ;
    PORT
      LAYER metal2 ;
      RECT 44.425 0.000 44.495 0.210 ;
    END
  END rw0_wd_in[185]
  PIN rw0_wd_in[186]
    DIRECTION INPUT ;
    USE SIGNAL ;
    SHAPE ABUTMENT ;
    PORT
      LAYER metal2 ;
      RECT 45.185 0.000 45.255 0.210 ;
    END
  END rw0_wd_in[186]
  PIN rw0_wd_in[187]
    DIRECTION INPUT ;
    USE SIGNAL ;
    SHAPE ABUTMENT ;
    PORT
      LAYER metal2 ;
      RECT 45.945 0.000 46.015 0.210 ;
    END
  END rw0_wd_in[187]
  PIN rw0_wd_in[188]
    DIRECTION INPUT ;
    USE SIGNAL ;
    SHAPE ABUTMENT ;
    PORT
      LAYER metal2 ;
      RECT 46.705 0.000 46.775 0.210 ;
    END
  END rw0_wd_in[188]
  PIN rw0_wd_in[189]
    DIRECTION INPUT ;
    USE SIGNAL ;
    SHAPE ABUTMENT ;
    PORT
      LAYER metal2 ;
      RECT 47.465 0.000 47.535 0.210 ;
    END
  END rw0_wd_in[189]
  PIN rw0_wd_in[190]
    DIRECTION INPUT ;
    USE SIGNAL ;
    SHAPE ABUTMENT ;
    PORT
      LAYER metal2 ;
      RECT 48.225 0.000 48.295 0.210 ;
    END
  END rw0_wd_in[190]
  PIN rw0_wd_in[191]
    DIRECTION INPUT ;
    USE SIGNAL ;
    SHAPE ABUTMENT ;
    PORT
      LAYER metal2 ;
      RECT 48.985 0.000 49.055 0.210 ;
    END
  END rw0_wd_in[191]
  PIN rw0_wd_in[192]
    DIRECTION INPUT ;
    USE SIGNAL ;
    SHAPE ABUTMENT ;
    PORT
      LAYER metal2 ;
      RECT 49.745 0.000 49.815 0.210 ;
    END
  END rw0_wd_in[192]
  PIN rw0_wd_in[193]
    DIRECTION INPUT ;
    USE SIGNAL ;
    SHAPE ABUTMENT ;
    PORT
      LAYER metal2 ;
      RECT 50.505 0.000 50.575 0.210 ;
    END
  END rw0_wd_in[193]
  PIN rw0_wd_in[194]
    DIRECTION INPUT ;
    USE SIGNAL ;
    SHAPE ABUTMENT ;
    PORT
      LAYER metal2 ;
      RECT 51.265 0.000 51.335 0.210 ;
    END
  END rw0_wd_in[194]
  PIN rw0_wd_in[195]
    DIRECTION INPUT ;
    USE SIGNAL ;
    SHAPE ABUTMENT ;
    PORT
      LAYER metal2 ;
      RECT 52.025 0.000 52.095 0.210 ;
    END
  END rw0_wd_in[195]
  PIN rw0_wd_in[196]
    DIRECTION INPUT ;
    USE SIGNAL ;
    SHAPE ABUTMENT ;
    PORT
      LAYER metal2 ;
      RECT 52.785 0.000 52.855 0.210 ;
    END
  END rw0_wd_in[196]
  PIN rw0_wd_in[197]
    DIRECTION INPUT ;
    USE SIGNAL ;
    SHAPE ABUTMENT ;
    PORT
      LAYER metal2 ;
      RECT 53.545 0.000 53.615 0.210 ;
    END
  END rw0_wd_in[197]
  PIN rw0_wd_in[198]
    DIRECTION INPUT ;
    USE SIGNAL ;
    SHAPE ABUTMENT ;
    PORT
      LAYER metal2 ;
      RECT 54.305 0.000 54.375 0.210 ;
    END
  END rw0_wd_in[198]
  PIN rw0_wd_in[199]
    DIRECTION INPUT ;
    USE SIGNAL ;
    SHAPE ABUTMENT ;
    PORT
      LAYER metal2 ;
      RECT 55.065 0.000 55.135 0.210 ;
    END
  END rw0_wd_in[199]
  PIN rw0_wd_in[200]
    DIRECTION INPUT ;
    USE SIGNAL ;
    SHAPE ABUTMENT ;
    PORT
      LAYER metal2 ;
      RECT 55.825 0.000 55.895 0.210 ;
    END
  END rw0_wd_in[200]
  PIN rw0_wd_in[201]
    DIRECTION INPUT ;
    USE SIGNAL ;
    SHAPE ABUTMENT ;
    PORT
      LAYER metal2 ;
      RECT 56.585 0.000 56.655 0.210 ;
    END
  END rw0_wd_in[201]
  PIN rw0_wd_in[202]
    DIRECTION INPUT ;
    USE SIGNAL ;
    SHAPE ABUTMENT ;
    PORT
      LAYER metal2 ;
      RECT 57.345 0.000 57.415 0.210 ;
    END
  END rw0_wd_in[202]
  PIN rw0_wd_in[203]
    DIRECTION INPUT ;
    USE SIGNAL ;
    SHAPE ABUTMENT ;
    PORT
      LAYER metal2 ;
      RECT 58.105 0.000 58.175 0.210 ;
    END
  END rw0_wd_in[203]
  PIN rw0_wd_in[204]
    DIRECTION INPUT ;
    USE SIGNAL ;
    SHAPE ABUTMENT ;
    PORT
      LAYER metal2 ;
      RECT 58.865 0.000 58.935 0.210 ;
    END
  END rw0_wd_in[204]
  PIN rw0_wd_in[205]
    DIRECTION INPUT ;
    USE SIGNAL ;
    SHAPE ABUTMENT ;
    PORT
      LAYER metal2 ;
      RECT 59.625 0.000 59.695 0.210 ;
    END
  END rw0_wd_in[205]
  PIN rw0_wd_in[206]
    DIRECTION INPUT ;
    USE SIGNAL ;
    SHAPE ABUTMENT ;
    PORT
      LAYER metal2 ;
      RECT 60.385 0.000 60.455 0.210 ;
    END
  END rw0_wd_in[206]
  PIN rw0_wd_in[207]
    DIRECTION INPUT ;
    USE SIGNAL ;
    SHAPE ABUTMENT ;
    PORT
      LAYER metal2 ;
      RECT 61.145 0.000 61.215 0.210 ;
    END
  END rw0_wd_in[207]
  PIN rw0_wd_in[208]
    DIRECTION INPUT ;
    USE SIGNAL ;
    SHAPE ABUTMENT ;
    PORT
      LAYER metal2 ;
      RECT 61.905 0.000 61.975 0.210 ;
    END
  END rw0_wd_in[208]
  PIN rw0_wd_in[209]
    DIRECTION INPUT ;
    USE SIGNAL ;
    SHAPE ABUTMENT ;
    PORT
      LAYER metal2 ;
      RECT 62.665 0.000 62.735 0.210 ;
    END
  END rw0_wd_in[209]
  PIN rw0_wd_in[210]
    DIRECTION INPUT ;
    USE SIGNAL ;
    SHAPE ABUTMENT ;
    PORT
      LAYER metal2 ;
      RECT 63.425 0.000 63.495 0.210 ;
    END
  END rw0_wd_in[210]
  PIN rw0_wd_in[211]
    DIRECTION INPUT ;
    USE SIGNAL ;
    SHAPE ABUTMENT ;
    PORT
      LAYER metal2 ;
      RECT 64.185 0.000 64.255 0.210 ;
    END
  END rw0_wd_in[211]
  PIN rw0_wd_in[212]
    DIRECTION INPUT ;
    USE SIGNAL ;
    SHAPE ABUTMENT ;
    PORT
      LAYER metal2 ;
      RECT 64.945 0.000 65.015 0.210 ;
    END
  END rw0_wd_in[212]
  PIN rw0_wd_in[213]
    DIRECTION INPUT ;
    USE SIGNAL ;
    SHAPE ABUTMENT ;
    PORT
      LAYER metal2 ;
      RECT 65.705 0.000 65.775 0.210 ;
    END
  END rw0_wd_in[213]
  PIN rw0_wd_in[214]
    DIRECTION INPUT ;
    USE SIGNAL ;
    SHAPE ABUTMENT ;
    PORT
      LAYER metal2 ;
      RECT 66.465 0.000 66.535 0.210 ;
    END
  END rw0_wd_in[214]
  PIN rw0_wd_in[215]
    DIRECTION INPUT ;
    USE SIGNAL ;
    SHAPE ABUTMENT ;
    PORT
      LAYER metal2 ;
      RECT 67.225 0.000 67.295 0.210 ;
    END
  END rw0_wd_in[215]
  PIN rw0_wd_in[216]
    DIRECTION INPUT ;
    USE SIGNAL ;
    SHAPE ABUTMENT ;
    PORT
      LAYER metal2 ;
      RECT 67.985 0.000 68.055 0.210 ;
    END
  END rw0_wd_in[216]
  PIN rw0_wd_in[217]
    DIRECTION INPUT ;
    USE SIGNAL ;
    SHAPE ABUTMENT ;
    PORT
      LAYER metal2 ;
      RECT 68.745 0.000 68.815 0.210 ;
    END
  END rw0_wd_in[217]
  PIN rw0_wd_in[218]
    DIRECTION INPUT ;
    USE SIGNAL ;
    SHAPE ABUTMENT ;
    PORT
      LAYER metal2 ;
      RECT 69.505 0.000 69.575 0.210 ;
    END
  END rw0_wd_in[218]
  PIN rw0_wd_in[219]
    DIRECTION INPUT ;
    USE SIGNAL ;
    SHAPE ABUTMENT ;
    PORT
      LAYER metal2 ;
      RECT 70.265 0.000 70.335 0.210 ;
    END
  END rw0_wd_in[219]
  PIN rw0_wd_in[220]
    DIRECTION INPUT ;
    USE SIGNAL ;
    SHAPE ABUTMENT ;
    PORT
      LAYER metal2 ;
      RECT 71.025 0.000 71.095 0.210 ;
    END
  END rw0_wd_in[220]
  PIN rw0_wd_in[221]
    DIRECTION INPUT ;
    USE SIGNAL ;
    SHAPE ABUTMENT ;
    PORT
      LAYER metal2 ;
      RECT 71.785 0.000 71.855 0.210 ;
    END
  END rw0_wd_in[221]
  PIN rw0_wd_in[222]
    DIRECTION INPUT ;
    USE SIGNAL ;
    SHAPE ABUTMENT ;
    PORT
      LAYER metal2 ;
      RECT 72.545 0.000 72.615 0.210 ;
    END
  END rw0_wd_in[222]
  PIN rw0_wd_in[223]
    DIRECTION INPUT ;
    USE SIGNAL ;
    SHAPE ABUTMENT ;
    PORT
      LAYER metal2 ;
      RECT 73.305 0.000 73.375 0.210 ;
    END
  END rw0_wd_in[223]
  PIN rw0_wd_in[224]
    DIRECTION INPUT ;
    USE SIGNAL ;
    SHAPE ABUTMENT ;
    PORT
      LAYER metal2 ;
      RECT 74.065 0.000 74.135 0.210 ;
    END
  END rw0_wd_in[224]
  PIN rw0_wd_in[225]
    DIRECTION INPUT ;
    USE SIGNAL ;
    SHAPE ABUTMENT ;
    PORT
      LAYER metal2 ;
      RECT 74.825 0.000 74.895 0.210 ;
    END
  END rw0_wd_in[225]
  PIN rw0_wd_in[226]
    DIRECTION INPUT ;
    USE SIGNAL ;
    SHAPE ABUTMENT ;
    PORT
      LAYER metal2 ;
      RECT 75.585 0.000 75.655 0.210 ;
    END
  END rw0_wd_in[226]
  PIN rw0_wd_in[227]
    DIRECTION INPUT ;
    USE SIGNAL ;
    SHAPE ABUTMENT ;
    PORT
      LAYER metal2 ;
      RECT 76.345 0.000 76.415 0.210 ;
    END
  END rw0_wd_in[227]
  PIN rw0_wd_in[228]
    DIRECTION INPUT ;
    USE SIGNAL ;
    SHAPE ABUTMENT ;
    PORT
      LAYER metal2 ;
      RECT 77.105 0.000 77.175 0.210 ;
    END
  END rw0_wd_in[228]
  PIN rw0_wd_in[229]
    DIRECTION INPUT ;
    USE SIGNAL ;
    SHAPE ABUTMENT ;
    PORT
      LAYER metal2 ;
      RECT 77.865 0.000 77.935 0.210 ;
    END
  END rw0_wd_in[229]
  PIN rw0_wd_in[230]
    DIRECTION INPUT ;
    USE SIGNAL ;
    SHAPE ABUTMENT ;
    PORT
      LAYER metal2 ;
      RECT 78.625 0.000 78.695 0.210 ;
    END
  END rw0_wd_in[230]
  PIN rw0_wd_in[231]
    DIRECTION INPUT ;
    USE SIGNAL ;
    SHAPE ABUTMENT ;
    PORT
      LAYER metal2 ;
      RECT 79.385 0.000 79.455 0.210 ;
    END
  END rw0_wd_in[231]
  PIN rw0_wd_in[232]
    DIRECTION INPUT ;
    USE SIGNAL ;
    SHAPE ABUTMENT ;
    PORT
      LAYER metal2 ;
      RECT 80.145 0.000 80.215 0.210 ;
    END
  END rw0_wd_in[232]
  PIN rw0_wd_in[233]
    DIRECTION INPUT ;
    USE SIGNAL ;
    SHAPE ABUTMENT ;
    PORT
      LAYER metal2 ;
      RECT 80.905 0.000 80.975 0.210 ;
    END
  END rw0_wd_in[233]
  PIN rw0_wd_in[234]
    DIRECTION INPUT ;
    USE SIGNAL ;
    SHAPE ABUTMENT ;
    PORT
      LAYER metal2 ;
      RECT 81.665 0.000 81.735 0.210 ;
    END
  END rw0_wd_in[234]
  PIN rw0_wd_in[235]
    DIRECTION INPUT ;
    USE SIGNAL ;
    SHAPE ABUTMENT ;
    PORT
      LAYER metal2 ;
      RECT 82.425 0.000 82.495 0.210 ;
    END
  END rw0_wd_in[235]
  PIN rw0_wd_in[236]
    DIRECTION INPUT ;
    USE SIGNAL ;
    SHAPE ABUTMENT ;
    PORT
      LAYER metal2 ;
      RECT 83.185 0.000 83.255 0.210 ;
    END
  END rw0_wd_in[236]
  PIN rw0_wd_in[237]
    DIRECTION INPUT ;
    USE SIGNAL ;
    SHAPE ABUTMENT ;
    PORT
      LAYER metal2 ;
      RECT 83.945 0.000 84.015 0.210 ;
    END
  END rw0_wd_in[237]
  PIN rw0_wd_in[238]
    DIRECTION INPUT ;
    USE SIGNAL ;
    SHAPE ABUTMENT ;
    PORT
      LAYER metal2 ;
      RECT 84.705 0.000 84.775 0.210 ;
    END
  END rw0_wd_in[238]
  PIN rw0_wd_in[239]
    DIRECTION INPUT ;
    USE SIGNAL ;
    SHAPE ABUTMENT ;
    PORT
      LAYER metal2 ;
      RECT 85.465 0.000 85.535 0.210 ;
    END
  END rw0_wd_in[239]
  PIN rw0_wd_in[240]
    DIRECTION INPUT ;
    USE SIGNAL ;
    SHAPE ABUTMENT ;
    PORT
      LAYER metal2 ;
      RECT 86.225 0.000 86.295 0.210 ;
    END
  END rw0_wd_in[240]
  PIN rw0_wd_in[241]
    DIRECTION INPUT ;
    USE SIGNAL ;
    SHAPE ABUTMENT ;
    PORT
      LAYER metal2 ;
      RECT 86.985 0.000 87.055 0.210 ;
    END
  END rw0_wd_in[241]
  PIN rw0_wd_in[242]
    DIRECTION INPUT ;
    USE SIGNAL ;
    SHAPE ABUTMENT ;
    PORT
      LAYER metal2 ;
      RECT 87.745 0.000 87.815 0.210 ;
    END
  END rw0_wd_in[242]
  PIN rw0_wd_in[243]
    DIRECTION INPUT ;
    USE SIGNAL ;
    SHAPE ABUTMENT ;
    PORT
      LAYER metal2 ;
      RECT 88.505 0.000 88.575 0.210 ;
    END
  END rw0_wd_in[243]
  PIN rw0_wd_in[244]
    DIRECTION INPUT ;
    USE SIGNAL ;
    SHAPE ABUTMENT ;
    PORT
      LAYER metal2 ;
      RECT 89.265 0.000 89.335 0.210 ;
    END
  END rw0_wd_in[244]
  PIN rw0_wd_in[245]
    DIRECTION INPUT ;
    USE SIGNAL ;
    SHAPE ABUTMENT ;
    PORT
      LAYER metal2 ;
      RECT 90.025 0.000 90.095 0.210 ;
    END
  END rw0_wd_in[245]
  PIN rw0_wd_in[246]
    DIRECTION INPUT ;
    USE SIGNAL ;
    SHAPE ABUTMENT ;
    PORT
      LAYER metal2 ;
      RECT 90.785 0.000 90.855 0.210 ;
    END
  END rw0_wd_in[246]
  PIN rw0_wd_in[247]
    DIRECTION INPUT ;
    USE SIGNAL ;
    SHAPE ABUTMENT ;
    PORT
      LAYER metal2 ;
      RECT 91.545 0.000 91.615 0.210 ;
    END
  END rw0_wd_in[247]
  PIN rw0_wd_in[248]
    DIRECTION INPUT ;
    USE SIGNAL ;
    SHAPE ABUTMENT ;
    PORT
      LAYER metal2 ;
      RECT 92.305 0.000 92.375 0.210 ;
    END
  END rw0_wd_in[248]
  PIN rw0_wd_in[249]
    DIRECTION INPUT ;
    USE SIGNAL ;
    SHAPE ABUTMENT ;
    PORT
      LAYER metal2 ;
      RECT 93.065 0.000 93.135 0.210 ;
    END
  END rw0_wd_in[249]
  PIN rw0_wd_in[250]
    DIRECTION INPUT ;
    USE SIGNAL ;
    SHAPE ABUTMENT ;
    PORT
      LAYER metal2 ;
      RECT 93.825 0.000 93.895 0.210 ;
    END
  END rw0_wd_in[250]
  PIN rw0_wd_in[251]
    DIRECTION INPUT ;
    USE SIGNAL ;
    SHAPE ABUTMENT ;
    PORT
      LAYER metal2 ;
      RECT 94.585 0.000 94.655 0.210 ;
    END
  END rw0_wd_in[251]
  PIN rw0_wd_in[252]
    DIRECTION INPUT ;
    USE SIGNAL ;
    SHAPE ABUTMENT ;
    PORT
      LAYER metal2 ;
      RECT 95.345 0.000 95.415 0.210 ;
    END
  END rw0_wd_in[252]
  PIN rw0_wd_in[253]
    DIRECTION INPUT ;
    USE SIGNAL ;
    SHAPE ABUTMENT ;
    PORT
      LAYER metal2 ;
      RECT 96.105 0.000 96.175 0.210 ;
    END
  END rw0_wd_in[253]
  PIN rw0_wd_in[254]
    DIRECTION INPUT ;
    USE SIGNAL ;
    SHAPE ABUTMENT ;
    PORT
      LAYER metal2 ;
      RECT 96.865 0.000 96.935 0.210 ;
    END
  END rw0_wd_in[254]
  PIN rw0_wd_in[255]
    DIRECTION INPUT ;
    USE SIGNAL ;
    SHAPE ABUTMENT ;
    PORT
      LAYER metal2 ;
      RECT 97.625 0.000 97.695 0.210 ;
    END
  END rw0_wd_in[255]
  PIN rw0_rd_out[0]
    DIRECTION OUTPUT ;
    USE SIGNAL ;
    SHAPE ABUTMENT ;
    PORT
      LAYER metal2 ;
      RECT 98.385 0.000 98.455 0.210 ;
    END
  END rw0_rd_out[0]
  PIN rw0_rd_out[1]
    DIRECTION OUTPUT ;
    USE SIGNAL ;
    SHAPE ABUTMENT ;
    PORT
      LAYER metal2 ;
      RECT 99.145 0.000 99.215 0.210 ;
    END
  END rw0_rd_out[1]
  PIN rw0_rd_out[2]
    DIRECTION OUTPUT ;
    USE SIGNAL ;
    SHAPE ABUTMENT ;
    PORT
      LAYER metal2 ;
      RECT 99.905 0.000 99.975 0.210 ;
    END
  END rw0_rd_out[2]
  PIN rw0_rd_out[3]
    DIRECTION OUTPUT ;
    USE SIGNAL ;
    SHAPE ABUTMENT ;
    PORT
      LAYER metal2 ;
      RECT 100.665 0.000 100.735 0.210 ;
    END
  END rw0_rd_out[3]
  PIN rw0_rd_out[4]
    DIRECTION OUTPUT ;
    USE SIGNAL ;
    SHAPE ABUTMENT ;
    PORT
      LAYER metal2 ;
      RECT 101.425 0.000 101.495 0.210 ;
    END
  END rw0_rd_out[4]
  PIN rw0_rd_out[5]
    DIRECTION OUTPUT ;
    USE SIGNAL ;
    SHAPE ABUTMENT ;
    PORT
      LAYER metal2 ;
      RECT 102.185 0.000 102.255 0.210 ;
    END
  END rw0_rd_out[5]
  PIN rw0_rd_out[6]
    DIRECTION OUTPUT ;
    USE SIGNAL ;
    SHAPE ABUTMENT ;
    PORT
      LAYER metal2 ;
      RECT 102.945 0.000 103.015 0.210 ;
    END
  END rw0_rd_out[6]
  PIN rw0_rd_out[7]
    DIRECTION OUTPUT ;
    USE SIGNAL ;
    SHAPE ABUTMENT ;
    PORT
      LAYER metal2 ;
      RECT 103.705 0.000 103.775 0.210 ;
    END
  END rw0_rd_out[7]
  PIN rw0_rd_out[8]
    DIRECTION OUTPUT ;
    USE SIGNAL ;
    SHAPE ABUTMENT ;
    PORT
      LAYER metal2 ;
      RECT 104.465 0.000 104.535 0.210 ;
    END
  END rw0_rd_out[8]
  PIN rw0_rd_out[9]
    DIRECTION OUTPUT ;
    USE SIGNAL ;
    SHAPE ABUTMENT ;
    PORT
      LAYER metal2 ;
      RECT 105.225 0.000 105.295 0.210 ;
    END
  END rw0_rd_out[9]
  PIN rw0_rd_out[10]
    DIRECTION OUTPUT ;
    USE SIGNAL ;
    SHAPE ABUTMENT ;
    PORT
      LAYER metal2 ;
      RECT 105.985 0.000 106.055 0.210 ;
    END
  END rw0_rd_out[10]
  PIN rw0_rd_out[11]
    DIRECTION OUTPUT ;
    USE SIGNAL ;
    SHAPE ABUTMENT ;
    PORT
      LAYER metal2 ;
      RECT 106.745 0.000 106.815 0.210 ;
    END
  END rw0_rd_out[11]
  PIN rw0_rd_out[12]
    DIRECTION OUTPUT ;
    USE SIGNAL ;
    SHAPE ABUTMENT ;
    PORT
      LAYER metal2 ;
      RECT 107.505 0.000 107.575 0.210 ;
    END
  END rw0_rd_out[12]
  PIN rw0_rd_out[13]
    DIRECTION OUTPUT ;
    USE SIGNAL ;
    SHAPE ABUTMENT ;
    PORT
      LAYER metal2 ;
      RECT 108.265 0.000 108.335 0.210 ;
    END
  END rw0_rd_out[13]
  PIN rw0_rd_out[14]
    DIRECTION OUTPUT ;
    USE SIGNAL ;
    SHAPE ABUTMENT ;
    PORT
      LAYER metal2 ;
      RECT 109.025 0.000 109.095 0.210 ;
    END
  END rw0_rd_out[14]
  PIN rw0_rd_out[15]
    DIRECTION OUTPUT ;
    USE SIGNAL ;
    SHAPE ABUTMENT ;
    PORT
      LAYER metal2 ;
      RECT 109.785 0.000 109.855 0.210 ;
    END
  END rw0_rd_out[15]
  PIN rw0_rd_out[16]
    DIRECTION OUTPUT ;
    USE SIGNAL ;
    SHAPE ABUTMENT ;
    PORT
      LAYER metal2 ;
      RECT 110.545 0.000 110.615 0.210 ;
    END
  END rw0_rd_out[16]
  PIN rw0_rd_out[17]
    DIRECTION OUTPUT ;
    USE SIGNAL ;
    SHAPE ABUTMENT ;
    PORT
      LAYER metal2 ;
      RECT 111.305 0.000 111.375 0.210 ;
    END
  END rw0_rd_out[17]
  PIN rw0_rd_out[18]
    DIRECTION OUTPUT ;
    USE SIGNAL ;
    SHAPE ABUTMENT ;
    PORT
      LAYER metal2 ;
      RECT 112.065 0.000 112.135 0.210 ;
    END
  END rw0_rd_out[18]
  PIN rw0_rd_out[19]
    DIRECTION OUTPUT ;
    USE SIGNAL ;
    SHAPE ABUTMENT ;
    PORT
      LAYER metal2 ;
      RECT 112.825 0.000 112.895 0.210 ;
    END
  END rw0_rd_out[19]
  PIN rw0_rd_out[20]
    DIRECTION OUTPUT ;
    USE SIGNAL ;
    SHAPE ABUTMENT ;
    PORT
      LAYER metal2 ;
      RECT 113.585 0.000 113.655 0.210 ;
    END
  END rw0_rd_out[20]
  PIN rw0_rd_out[21]
    DIRECTION OUTPUT ;
    USE SIGNAL ;
    SHAPE ABUTMENT ;
    PORT
      LAYER metal2 ;
      RECT 114.345 0.000 114.415 0.210 ;
    END
  END rw0_rd_out[21]
  PIN rw0_rd_out[22]
    DIRECTION OUTPUT ;
    USE SIGNAL ;
    SHAPE ABUTMENT ;
    PORT
      LAYER metal2 ;
      RECT 115.105 0.000 115.175 0.210 ;
    END
  END rw0_rd_out[22]
  PIN rw0_rd_out[23]
    DIRECTION OUTPUT ;
    USE SIGNAL ;
    SHAPE ABUTMENT ;
    PORT
      LAYER metal2 ;
      RECT 115.865 0.000 115.935 0.210 ;
    END
  END rw0_rd_out[23]
  PIN rw0_rd_out[24]
    DIRECTION OUTPUT ;
    USE SIGNAL ;
    SHAPE ABUTMENT ;
    PORT
      LAYER metal2 ;
      RECT 116.625 0.000 116.695 0.210 ;
    END
  END rw0_rd_out[24]
  PIN rw0_rd_out[25]
    DIRECTION OUTPUT ;
    USE SIGNAL ;
    SHAPE ABUTMENT ;
    PORT
      LAYER metal2 ;
      RECT 117.385 0.000 117.455 0.210 ;
    END
  END rw0_rd_out[25]
  PIN rw0_rd_out[26]
    DIRECTION OUTPUT ;
    USE SIGNAL ;
    SHAPE ABUTMENT ;
    PORT
      LAYER metal2 ;
      RECT 118.145 0.000 118.215 0.210 ;
    END
  END rw0_rd_out[26]
  PIN rw0_rd_out[27]
    DIRECTION OUTPUT ;
    USE SIGNAL ;
    SHAPE ABUTMENT ;
    PORT
      LAYER metal2 ;
      RECT 118.905 0.000 118.975 0.210 ;
    END
  END rw0_rd_out[27]
  PIN rw0_rd_out[28]
    DIRECTION OUTPUT ;
    USE SIGNAL ;
    SHAPE ABUTMENT ;
    PORT
      LAYER metal2 ;
      RECT 119.665 0.000 119.735 0.210 ;
    END
  END rw0_rd_out[28]
  PIN rw0_rd_out[29]
    DIRECTION OUTPUT ;
    USE SIGNAL ;
    SHAPE ABUTMENT ;
    PORT
      LAYER metal2 ;
      RECT 120.425 0.000 120.495 0.210 ;
    END
  END rw0_rd_out[29]
  PIN rw0_rd_out[30]
    DIRECTION OUTPUT ;
    USE SIGNAL ;
    SHAPE ABUTMENT ;
    PORT
      LAYER metal2 ;
      RECT 121.185 0.000 121.255 0.210 ;
    END
  END rw0_rd_out[30]
  PIN rw0_rd_out[31]
    DIRECTION OUTPUT ;
    USE SIGNAL ;
    SHAPE ABUTMENT ;
    PORT
      LAYER metal2 ;
      RECT 121.945 0.000 122.015 0.210 ;
    END
  END rw0_rd_out[31]
  PIN rw0_rd_out[32]
    DIRECTION OUTPUT ;
    USE SIGNAL ;
    SHAPE ABUTMENT ;
    PORT
      LAYER metal2 ;
      RECT 122.705 0.000 122.775 0.210 ;
    END
  END rw0_rd_out[32]
  PIN rw0_rd_out[33]
    DIRECTION OUTPUT ;
    USE SIGNAL ;
    SHAPE ABUTMENT ;
    PORT
      LAYER metal2 ;
      RECT 123.465 0.000 123.535 0.210 ;
    END
  END rw0_rd_out[33]
  PIN rw0_rd_out[34]
    DIRECTION OUTPUT ;
    USE SIGNAL ;
    SHAPE ABUTMENT ;
    PORT
      LAYER metal2 ;
      RECT 124.225 0.000 124.295 0.210 ;
    END
  END rw0_rd_out[34]
  PIN rw0_rd_out[35]
    DIRECTION OUTPUT ;
    USE SIGNAL ;
    SHAPE ABUTMENT ;
    PORT
      LAYER metal2 ;
      RECT 124.985 0.000 125.055 0.210 ;
    END
  END rw0_rd_out[35]
  PIN rw0_rd_out[36]
    DIRECTION OUTPUT ;
    USE SIGNAL ;
    SHAPE ABUTMENT ;
    PORT
      LAYER metal2 ;
      RECT 125.745 0.000 125.815 0.210 ;
    END
  END rw0_rd_out[36]
  PIN rw0_rd_out[37]
    DIRECTION OUTPUT ;
    USE SIGNAL ;
    SHAPE ABUTMENT ;
    PORT
      LAYER metal2 ;
      RECT 126.505 0.000 126.575 0.210 ;
    END
  END rw0_rd_out[37]
  PIN rw0_rd_out[38]
    DIRECTION OUTPUT ;
    USE SIGNAL ;
    SHAPE ABUTMENT ;
    PORT
      LAYER metal2 ;
      RECT 127.265 0.000 127.335 0.210 ;
    END
  END rw0_rd_out[38]
  PIN rw0_rd_out[39]
    DIRECTION OUTPUT ;
    USE SIGNAL ;
    SHAPE ABUTMENT ;
    PORT
      LAYER metal2 ;
      RECT 128.025 0.000 128.095 0.210 ;
    END
  END rw0_rd_out[39]
  PIN rw0_rd_out[40]
    DIRECTION OUTPUT ;
    USE SIGNAL ;
    SHAPE ABUTMENT ;
    PORT
      LAYER metal2 ;
      RECT 128.785 0.000 128.855 0.210 ;
    END
  END rw0_rd_out[40]
  PIN rw0_rd_out[41]
    DIRECTION OUTPUT ;
    USE SIGNAL ;
    SHAPE ABUTMENT ;
    PORT
      LAYER metal2 ;
      RECT 129.545 0.000 129.615 0.210 ;
    END
  END rw0_rd_out[41]
  PIN rw0_rd_out[42]
    DIRECTION OUTPUT ;
    USE SIGNAL ;
    SHAPE ABUTMENT ;
    PORT
      LAYER metal2 ;
      RECT 130.305 0.000 130.375 0.210 ;
    END
  END rw0_rd_out[42]
  PIN rw0_rd_out[43]
    DIRECTION OUTPUT ;
    USE SIGNAL ;
    SHAPE ABUTMENT ;
    PORT
      LAYER metal2 ;
      RECT 131.065 0.000 131.135 0.210 ;
    END
  END rw0_rd_out[43]
  PIN rw0_rd_out[44]
    DIRECTION OUTPUT ;
    USE SIGNAL ;
    SHAPE ABUTMENT ;
    PORT
      LAYER metal2 ;
      RECT 131.825 0.000 131.895 0.210 ;
    END
  END rw0_rd_out[44]
  PIN rw0_rd_out[45]
    DIRECTION OUTPUT ;
    USE SIGNAL ;
    SHAPE ABUTMENT ;
    PORT
      LAYER metal2 ;
      RECT 132.585 0.000 132.655 0.210 ;
    END
  END rw0_rd_out[45]
  PIN rw0_rd_out[46]
    DIRECTION OUTPUT ;
    USE SIGNAL ;
    SHAPE ABUTMENT ;
    PORT
      LAYER metal2 ;
      RECT 133.345 0.000 133.415 0.210 ;
    END
  END rw0_rd_out[46]
  PIN rw0_rd_out[47]
    DIRECTION OUTPUT ;
    USE SIGNAL ;
    SHAPE ABUTMENT ;
    PORT
      LAYER metal2 ;
      RECT 134.105 0.000 134.175 0.210 ;
    END
  END rw0_rd_out[47]
  PIN rw0_rd_out[48]
    DIRECTION OUTPUT ;
    USE SIGNAL ;
    SHAPE ABUTMENT ;
    PORT
      LAYER metal2 ;
      RECT 134.865 0.000 134.935 0.210 ;
    END
  END rw0_rd_out[48]
  PIN rw0_rd_out[49]
    DIRECTION OUTPUT ;
    USE SIGNAL ;
    SHAPE ABUTMENT ;
    PORT
      LAYER metal2 ;
      RECT 135.625 0.000 135.695 0.210 ;
    END
  END rw0_rd_out[49]
  PIN rw0_rd_out[50]
    DIRECTION OUTPUT ;
    USE SIGNAL ;
    SHAPE ABUTMENT ;
    PORT
      LAYER metal2 ;
      RECT 136.385 0.000 136.455 0.210 ;
    END
  END rw0_rd_out[50]
  PIN rw0_rd_out[51]
    DIRECTION OUTPUT ;
    USE SIGNAL ;
    SHAPE ABUTMENT ;
    PORT
      LAYER metal2 ;
      RECT 137.145 0.000 137.215 0.210 ;
    END
  END rw0_rd_out[51]
  PIN rw0_rd_out[52]
    DIRECTION OUTPUT ;
    USE SIGNAL ;
    SHAPE ABUTMENT ;
    PORT
      LAYER metal2 ;
      RECT 137.905 0.000 137.975 0.210 ;
    END
  END rw0_rd_out[52]
  PIN rw0_rd_out[53]
    DIRECTION OUTPUT ;
    USE SIGNAL ;
    SHAPE ABUTMENT ;
    PORT
      LAYER metal2 ;
      RECT 138.665 0.000 138.735 0.210 ;
    END
  END rw0_rd_out[53]
  PIN rw0_rd_out[54]
    DIRECTION OUTPUT ;
    USE SIGNAL ;
    SHAPE ABUTMENT ;
    PORT
      LAYER metal2 ;
      RECT 139.425 0.000 139.495 0.210 ;
    END
  END rw0_rd_out[54]
  PIN rw0_rd_out[55]
    DIRECTION OUTPUT ;
    USE SIGNAL ;
    SHAPE ABUTMENT ;
    PORT
      LAYER metal2 ;
      RECT 140.185 0.000 140.255 0.210 ;
    END
  END rw0_rd_out[55]
  PIN rw0_rd_out[56]
    DIRECTION OUTPUT ;
    USE SIGNAL ;
    SHAPE ABUTMENT ;
    PORT
      LAYER metal2 ;
      RECT 140.945 0.000 141.015 0.210 ;
    END
  END rw0_rd_out[56]
  PIN rw0_rd_out[57]
    DIRECTION OUTPUT ;
    USE SIGNAL ;
    SHAPE ABUTMENT ;
    PORT
      LAYER metal2 ;
      RECT 141.705 0.000 141.775 0.210 ;
    END
  END rw0_rd_out[57]
  PIN rw0_rd_out[58]
    DIRECTION OUTPUT ;
    USE SIGNAL ;
    SHAPE ABUTMENT ;
    PORT
      LAYER metal2 ;
      RECT 142.465 0.000 142.535 0.210 ;
    END
  END rw0_rd_out[58]
  PIN rw0_rd_out[59]
    DIRECTION OUTPUT ;
    USE SIGNAL ;
    SHAPE ABUTMENT ;
    PORT
      LAYER metal2 ;
      RECT 143.225 0.000 143.295 0.210 ;
    END
  END rw0_rd_out[59]
  PIN rw0_rd_out[60]
    DIRECTION OUTPUT ;
    USE SIGNAL ;
    SHAPE ABUTMENT ;
    PORT
      LAYER metal2 ;
      RECT 143.985 0.000 144.055 0.210 ;
    END
  END rw0_rd_out[60]
  PIN rw0_rd_out[61]
    DIRECTION OUTPUT ;
    USE SIGNAL ;
    SHAPE ABUTMENT ;
    PORT
      LAYER metal2 ;
      RECT 144.745 0.000 144.815 0.210 ;
    END
  END rw0_rd_out[61]
  PIN rw0_rd_out[62]
    DIRECTION OUTPUT ;
    USE SIGNAL ;
    SHAPE ABUTMENT ;
    PORT
      LAYER metal2 ;
      RECT 145.505 0.000 145.575 0.210 ;
    END
  END rw0_rd_out[62]
  PIN rw0_rd_out[63]
    DIRECTION OUTPUT ;
    USE SIGNAL ;
    SHAPE ABUTMENT ;
    PORT
      LAYER metal2 ;
      RECT 146.265 0.000 146.335 0.210 ;
    END
  END rw0_rd_out[63]
  PIN rw0_rd_out[64]
    DIRECTION OUTPUT ;
    USE SIGNAL ;
    SHAPE ABUTMENT ;
    PORT
      LAYER metal2 ;
      RECT 147.025 0.000 147.095 0.210 ;
    END
  END rw0_rd_out[64]
  PIN rw0_rd_out[65]
    DIRECTION OUTPUT ;
    USE SIGNAL ;
    SHAPE ABUTMENT ;
    PORT
      LAYER metal2 ;
      RECT 147.785 0.000 147.855 0.210 ;
    END
  END rw0_rd_out[65]
  PIN rw0_rd_out[66]
    DIRECTION OUTPUT ;
    USE SIGNAL ;
    SHAPE ABUTMENT ;
    PORT
      LAYER metal2 ;
      RECT 148.545 0.000 148.615 0.210 ;
    END
  END rw0_rd_out[66]
  PIN rw0_rd_out[67]
    DIRECTION OUTPUT ;
    USE SIGNAL ;
    SHAPE ABUTMENT ;
    PORT
      LAYER metal2 ;
      RECT 149.305 0.000 149.375 0.210 ;
    END
  END rw0_rd_out[67]
  PIN rw0_rd_out[68]
    DIRECTION OUTPUT ;
    USE SIGNAL ;
    SHAPE ABUTMENT ;
    PORT
      LAYER metal2 ;
      RECT 150.065 0.000 150.135 0.210 ;
    END
  END rw0_rd_out[68]
  PIN rw0_rd_out[69]
    DIRECTION OUTPUT ;
    USE SIGNAL ;
    SHAPE ABUTMENT ;
    PORT
      LAYER metal2 ;
      RECT 150.825 0.000 150.895 0.210 ;
    END
  END rw0_rd_out[69]
  PIN rw0_rd_out[70]
    DIRECTION OUTPUT ;
    USE SIGNAL ;
    SHAPE ABUTMENT ;
    PORT
      LAYER metal2 ;
      RECT 151.585 0.000 151.655 0.210 ;
    END
  END rw0_rd_out[70]
  PIN rw0_rd_out[71]
    DIRECTION OUTPUT ;
    USE SIGNAL ;
    SHAPE ABUTMENT ;
    PORT
      LAYER metal2 ;
      RECT 152.345 0.000 152.415 0.210 ;
    END
  END rw0_rd_out[71]
  PIN rw0_rd_out[72]
    DIRECTION OUTPUT ;
    USE SIGNAL ;
    SHAPE ABUTMENT ;
    PORT
      LAYER metal2 ;
      RECT 153.105 0.000 153.175 0.210 ;
    END
  END rw0_rd_out[72]
  PIN rw0_rd_out[73]
    DIRECTION OUTPUT ;
    USE SIGNAL ;
    SHAPE ABUTMENT ;
    PORT
      LAYER metal2 ;
      RECT 153.865 0.000 153.935 0.210 ;
    END
  END rw0_rd_out[73]
  PIN rw0_rd_out[74]
    DIRECTION OUTPUT ;
    USE SIGNAL ;
    SHAPE ABUTMENT ;
    PORT
      LAYER metal2 ;
      RECT 154.625 0.000 154.695 0.210 ;
    END
  END rw0_rd_out[74]
  PIN rw0_rd_out[75]
    DIRECTION OUTPUT ;
    USE SIGNAL ;
    SHAPE ABUTMENT ;
    PORT
      LAYER metal2 ;
      RECT 155.385 0.000 155.455 0.210 ;
    END
  END rw0_rd_out[75]
  PIN rw0_rd_out[76]
    DIRECTION OUTPUT ;
    USE SIGNAL ;
    SHAPE ABUTMENT ;
    PORT
      LAYER metal2 ;
      RECT 156.145 0.000 156.215 0.210 ;
    END
  END rw0_rd_out[76]
  PIN rw0_rd_out[77]
    DIRECTION OUTPUT ;
    USE SIGNAL ;
    SHAPE ABUTMENT ;
    PORT
      LAYER metal2 ;
      RECT 156.905 0.000 156.975 0.210 ;
    END
  END rw0_rd_out[77]
  PIN rw0_rd_out[78]
    DIRECTION OUTPUT ;
    USE SIGNAL ;
    SHAPE ABUTMENT ;
    PORT
      LAYER metal2 ;
      RECT 157.665 0.000 157.735 0.210 ;
    END
  END rw0_rd_out[78]
  PIN rw0_rd_out[79]
    DIRECTION OUTPUT ;
    USE SIGNAL ;
    SHAPE ABUTMENT ;
    PORT
      LAYER metal2 ;
      RECT 158.425 0.000 158.495 0.210 ;
    END
  END rw0_rd_out[79]
  PIN rw0_rd_out[80]
    DIRECTION OUTPUT ;
    USE SIGNAL ;
    SHAPE ABUTMENT ;
    PORT
      LAYER metal2 ;
      RECT 159.185 0.000 159.255 0.210 ;
    END
  END rw0_rd_out[80]
  PIN rw0_rd_out[81]
    DIRECTION OUTPUT ;
    USE SIGNAL ;
    SHAPE ABUTMENT ;
    PORT
      LAYER metal2 ;
      RECT 159.945 0.000 160.015 0.210 ;
    END
  END rw0_rd_out[81]
  PIN rw0_rd_out[82]
    DIRECTION OUTPUT ;
    USE SIGNAL ;
    SHAPE ABUTMENT ;
    PORT
      LAYER metal2 ;
      RECT 160.705 0.000 160.775 0.210 ;
    END
  END rw0_rd_out[82]
  PIN rw0_rd_out[83]
    DIRECTION OUTPUT ;
    USE SIGNAL ;
    SHAPE ABUTMENT ;
    PORT
      LAYER metal2 ;
      RECT 161.465 0.000 161.535 0.210 ;
    END
  END rw0_rd_out[83]
  PIN rw0_rd_out[84]
    DIRECTION OUTPUT ;
    USE SIGNAL ;
    SHAPE ABUTMENT ;
    PORT
      LAYER metal2 ;
      RECT 162.225 0.000 162.295 0.210 ;
    END
  END rw0_rd_out[84]
  PIN rw0_rd_out[85]
    DIRECTION OUTPUT ;
    USE SIGNAL ;
    SHAPE ABUTMENT ;
    PORT
      LAYER metal2 ;
      RECT 162.985 0.000 163.055 0.210 ;
    END
  END rw0_rd_out[85]
  PIN rw0_rd_out[86]
    DIRECTION OUTPUT ;
    USE SIGNAL ;
    SHAPE ABUTMENT ;
    PORT
      LAYER metal2 ;
      RECT 163.745 0.000 163.815 0.210 ;
    END
  END rw0_rd_out[86]
  PIN rw0_rd_out[87]
    DIRECTION OUTPUT ;
    USE SIGNAL ;
    SHAPE ABUTMENT ;
    PORT
      LAYER metal2 ;
      RECT 164.505 0.000 164.575 0.210 ;
    END
  END rw0_rd_out[87]
  PIN rw0_rd_out[88]
    DIRECTION OUTPUT ;
    USE SIGNAL ;
    SHAPE ABUTMENT ;
    PORT
      LAYER metal2 ;
      RECT 165.265 0.000 165.335 0.210 ;
    END
  END rw0_rd_out[88]
  PIN rw0_rd_out[89]
    DIRECTION OUTPUT ;
    USE SIGNAL ;
    SHAPE ABUTMENT ;
    PORT
      LAYER metal2 ;
      RECT 166.025 0.000 166.095 0.210 ;
    END
  END rw0_rd_out[89]
  PIN rw0_rd_out[90]
    DIRECTION OUTPUT ;
    USE SIGNAL ;
    SHAPE ABUTMENT ;
    PORT
      LAYER metal2 ;
      RECT 166.785 0.000 166.855 0.210 ;
    END
  END rw0_rd_out[90]
  PIN rw0_rd_out[91]
    DIRECTION OUTPUT ;
    USE SIGNAL ;
    SHAPE ABUTMENT ;
    PORT
      LAYER metal2 ;
      RECT 167.545 0.000 167.615 0.210 ;
    END
  END rw0_rd_out[91]
  PIN rw0_rd_out[92]
    DIRECTION OUTPUT ;
    USE SIGNAL ;
    SHAPE ABUTMENT ;
    PORT
      LAYER metal2 ;
      RECT 168.305 0.000 168.375 0.210 ;
    END
  END rw0_rd_out[92]
  PIN rw0_rd_out[93]
    DIRECTION OUTPUT ;
    USE SIGNAL ;
    SHAPE ABUTMENT ;
    PORT
      LAYER metal2 ;
      RECT 169.065 0.000 169.135 0.210 ;
    END
  END rw0_rd_out[93]
  PIN rw0_rd_out[94]
    DIRECTION OUTPUT ;
    USE SIGNAL ;
    SHAPE ABUTMENT ;
    PORT
      LAYER metal2 ;
      RECT 169.825 0.000 169.895 0.210 ;
    END
  END rw0_rd_out[94]
  PIN rw0_rd_out[95]
    DIRECTION OUTPUT ;
    USE SIGNAL ;
    SHAPE ABUTMENT ;
    PORT
      LAYER metal2 ;
      RECT 170.585 0.000 170.655 0.210 ;
    END
  END rw0_rd_out[95]
  PIN rw0_rd_out[96]
    DIRECTION OUTPUT ;
    USE SIGNAL ;
    SHAPE ABUTMENT ;
    PORT
      LAYER metal2 ;
      RECT 171.345 0.000 171.415 0.210 ;
    END
  END rw0_rd_out[96]
  PIN rw0_rd_out[97]
    DIRECTION OUTPUT ;
    USE SIGNAL ;
    SHAPE ABUTMENT ;
    PORT
      LAYER metal2 ;
      RECT 172.105 0.000 172.175 0.210 ;
    END
  END rw0_rd_out[97]
  PIN rw0_rd_out[98]
    DIRECTION OUTPUT ;
    USE SIGNAL ;
    SHAPE ABUTMENT ;
    PORT
      LAYER metal2 ;
      RECT 172.865 0.000 172.935 0.210 ;
    END
  END rw0_rd_out[98]
  PIN rw0_rd_out[99]
    DIRECTION OUTPUT ;
    USE SIGNAL ;
    SHAPE ABUTMENT ;
    PORT
      LAYER metal2 ;
      RECT 173.625 0.000 173.695 0.210 ;
    END
  END rw0_rd_out[99]
  PIN rw0_rd_out[100]
    DIRECTION OUTPUT ;
    USE SIGNAL ;
    SHAPE ABUTMENT ;
    PORT
      LAYER metal2 ;
      RECT 174.385 0.000 174.455 0.210 ;
    END
  END rw0_rd_out[100]
  PIN rw0_rd_out[101]
    DIRECTION OUTPUT ;
    USE SIGNAL ;
    SHAPE ABUTMENT ;
    PORT
      LAYER metal2 ;
      RECT 175.145 0.000 175.215 0.210 ;
    END
  END rw0_rd_out[101]
  PIN rw0_rd_out[102]
    DIRECTION OUTPUT ;
    USE SIGNAL ;
    SHAPE ABUTMENT ;
    PORT
      LAYER metal2 ;
      RECT 175.905 0.000 175.975 0.210 ;
    END
  END rw0_rd_out[102]
  PIN rw0_rd_out[103]
    DIRECTION OUTPUT ;
    USE SIGNAL ;
    SHAPE ABUTMENT ;
    PORT
      LAYER metal2 ;
      RECT 176.665 0.000 176.735 0.210 ;
    END
  END rw0_rd_out[103]
  PIN rw0_rd_out[104]
    DIRECTION OUTPUT ;
    USE SIGNAL ;
    SHAPE ABUTMENT ;
    PORT
      LAYER metal2 ;
      RECT 177.425 0.000 177.495 0.210 ;
    END
  END rw0_rd_out[104]
  PIN rw0_rd_out[105]
    DIRECTION OUTPUT ;
    USE SIGNAL ;
    SHAPE ABUTMENT ;
    PORT
      LAYER metal2 ;
      RECT 178.185 0.000 178.255 0.210 ;
    END
  END rw0_rd_out[105]
  PIN rw0_rd_out[106]
    DIRECTION OUTPUT ;
    USE SIGNAL ;
    SHAPE ABUTMENT ;
    PORT
      LAYER metal2 ;
      RECT 178.945 0.000 179.015 0.210 ;
    END
  END rw0_rd_out[106]
  PIN rw0_rd_out[107]
    DIRECTION OUTPUT ;
    USE SIGNAL ;
    SHAPE ABUTMENT ;
    PORT
      LAYER metal2 ;
      RECT 179.705 0.000 179.775 0.210 ;
    END
  END rw0_rd_out[107]
  PIN rw0_rd_out[108]
    DIRECTION OUTPUT ;
    USE SIGNAL ;
    SHAPE ABUTMENT ;
    PORT
      LAYER metal2 ;
      RECT 180.465 0.000 180.535 0.210 ;
    END
  END rw0_rd_out[108]
  PIN rw0_rd_out[109]
    DIRECTION OUTPUT ;
    USE SIGNAL ;
    SHAPE ABUTMENT ;
    PORT
      LAYER metal2 ;
      RECT 181.225 0.000 181.295 0.210 ;
    END
  END rw0_rd_out[109]
  PIN rw0_rd_out[110]
    DIRECTION OUTPUT ;
    USE SIGNAL ;
    SHAPE ABUTMENT ;
    PORT
      LAYER metal2 ;
      RECT 181.985 0.000 182.055 0.210 ;
    END
  END rw0_rd_out[110]
  PIN rw0_rd_out[111]
    DIRECTION OUTPUT ;
    USE SIGNAL ;
    SHAPE ABUTMENT ;
    PORT
      LAYER metal2 ;
      RECT 182.745 0.000 182.815 0.210 ;
    END
  END rw0_rd_out[111]
  PIN rw0_rd_out[112]
    DIRECTION OUTPUT ;
    USE SIGNAL ;
    SHAPE ABUTMENT ;
    PORT
      LAYER metal2 ;
      RECT 183.505 0.000 183.575 0.210 ;
    END
  END rw0_rd_out[112]
  PIN rw0_rd_out[113]
    DIRECTION OUTPUT ;
    USE SIGNAL ;
    SHAPE ABUTMENT ;
    PORT
      LAYER metal2 ;
      RECT 184.265 0.000 184.335 0.210 ;
    END
  END rw0_rd_out[113]
  PIN rw0_rd_out[114]
    DIRECTION OUTPUT ;
    USE SIGNAL ;
    SHAPE ABUTMENT ;
    PORT
      LAYER metal2 ;
      RECT 185.025 0.000 185.095 0.210 ;
    END
  END rw0_rd_out[114]
  PIN rw0_rd_out[115]
    DIRECTION OUTPUT ;
    USE SIGNAL ;
    SHAPE ABUTMENT ;
    PORT
      LAYER metal2 ;
      RECT 185.785 0.000 185.855 0.210 ;
    END
  END rw0_rd_out[115]
  PIN rw0_rd_out[116]
    DIRECTION OUTPUT ;
    USE SIGNAL ;
    SHAPE ABUTMENT ;
    PORT
      LAYER metal2 ;
      RECT 186.545 0.000 186.615 0.210 ;
    END
  END rw0_rd_out[116]
  PIN rw0_rd_out[117]
    DIRECTION OUTPUT ;
    USE SIGNAL ;
    SHAPE ABUTMENT ;
    PORT
      LAYER metal2 ;
      RECT 187.305 0.000 187.375 0.210 ;
    END
  END rw0_rd_out[117]
  PIN rw0_rd_out[118]
    DIRECTION OUTPUT ;
    USE SIGNAL ;
    SHAPE ABUTMENT ;
    PORT
      LAYER metal2 ;
      RECT 188.065 0.000 188.135 0.210 ;
    END
  END rw0_rd_out[118]
  PIN rw0_rd_out[119]
    DIRECTION OUTPUT ;
    USE SIGNAL ;
    SHAPE ABUTMENT ;
    PORT
      LAYER metal2 ;
      RECT 188.825 0.000 188.895 0.210 ;
    END
  END rw0_rd_out[119]
  PIN rw0_rd_out[120]
    DIRECTION OUTPUT ;
    USE SIGNAL ;
    SHAPE ABUTMENT ;
    PORT
      LAYER metal2 ;
      RECT 189.585 0.000 189.655 0.210 ;
    END
  END rw0_rd_out[120]
  PIN rw0_rd_out[121]
    DIRECTION OUTPUT ;
    USE SIGNAL ;
    SHAPE ABUTMENT ;
    PORT
      LAYER metal2 ;
      RECT 190.345 0.000 190.415 0.210 ;
    END
  END rw0_rd_out[121]
  PIN rw0_rd_out[122]
    DIRECTION OUTPUT ;
    USE SIGNAL ;
    SHAPE ABUTMENT ;
    PORT
      LAYER metal2 ;
      RECT 191.105 0.000 191.175 0.210 ;
    END
  END rw0_rd_out[122]
  PIN rw0_rd_out[123]
    DIRECTION OUTPUT ;
    USE SIGNAL ;
    SHAPE ABUTMENT ;
    PORT
      LAYER metal2 ;
      RECT 191.865 0.000 191.935 0.210 ;
    END
  END rw0_rd_out[123]
  PIN rw0_rd_out[124]
    DIRECTION OUTPUT ;
    USE SIGNAL ;
    SHAPE ABUTMENT ;
    PORT
      LAYER metal2 ;
      RECT 192.625 0.000 192.695 0.210 ;
    END
  END rw0_rd_out[124]
  PIN rw0_rd_out[125]
    DIRECTION OUTPUT ;
    USE SIGNAL ;
    SHAPE ABUTMENT ;
    PORT
      LAYER metal2 ;
      RECT 193.385 0.000 193.455 0.210 ;
    END
  END rw0_rd_out[125]
  PIN rw0_rd_out[126]
    DIRECTION OUTPUT ;
    USE SIGNAL ;
    SHAPE ABUTMENT ;
    PORT
      LAYER metal2 ;
      RECT 194.145 0.000 194.215 0.210 ;
    END
  END rw0_rd_out[126]
  PIN rw0_rd_out[127]
    DIRECTION OUTPUT ;
    USE SIGNAL ;
    SHAPE ABUTMENT ;
    PORT
      LAYER metal2 ;
      RECT 194.905 0.000 194.975 0.210 ;
    END
  END rw0_rd_out[127]
  PIN rw0_rd_out[128]
    DIRECTION OUTPUT ;
    USE SIGNAL ;
    SHAPE ABUTMENT ;
    PORT
      LAYER metal2 ;
      RECT 1.105 236.390 1.175 236.600 ;
    END
  END rw0_rd_out[128]
  PIN rw0_rd_out[129]
    DIRECTION OUTPUT ;
    USE SIGNAL ;
    SHAPE ABUTMENT ;
    PORT
      LAYER metal2 ;
      RECT 2.815 236.390 2.885 236.600 ;
    END
  END rw0_rd_out[129]
  PIN rw0_rd_out[130]
    DIRECTION OUTPUT ;
    USE SIGNAL ;
    SHAPE ABUTMENT ;
    PORT
      LAYER metal2 ;
      RECT 4.525 236.390 4.595 236.600 ;
    END
  END rw0_rd_out[130]
  PIN rw0_rd_out[131]
    DIRECTION OUTPUT ;
    USE SIGNAL ;
    SHAPE ABUTMENT ;
    PORT
      LAYER metal2 ;
      RECT 6.235 236.390 6.305 236.600 ;
    END
  END rw0_rd_out[131]
  PIN rw0_rd_out[132]
    DIRECTION OUTPUT ;
    USE SIGNAL ;
    SHAPE ABUTMENT ;
    PORT
      LAYER metal2 ;
      RECT 7.945 236.390 8.015 236.600 ;
    END
  END rw0_rd_out[132]
  PIN rw0_rd_out[133]
    DIRECTION OUTPUT ;
    USE SIGNAL ;
    SHAPE ABUTMENT ;
    PORT
      LAYER metal2 ;
      RECT 9.655 236.390 9.725 236.600 ;
    END
  END rw0_rd_out[133]
  PIN rw0_rd_out[134]
    DIRECTION OUTPUT ;
    USE SIGNAL ;
    SHAPE ABUTMENT ;
    PORT
      LAYER metal2 ;
      RECT 11.365 236.390 11.435 236.600 ;
    END
  END rw0_rd_out[134]
  PIN rw0_rd_out[135]
    DIRECTION OUTPUT ;
    USE SIGNAL ;
    SHAPE ABUTMENT ;
    PORT
      LAYER metal2 ;
      RECT 13.075 236.390 13.145 236.600 ;
    END
  END rw0_rd_out[135]
  PIN rw0_rd_out[136]
    DIRECTION OUTPUT ;
    USE SIGNAL ;
    SHAPE ABUTMENT ;
    PORT
      LAYER metal2 ;
      RECT 14.785 236.390 14.855 236.600 ;
    END
  END rw0_rd_out[136]
  PIN rw0_rd_out[137]
    DIRECTION OUTPUT ;
    USE SIGNAL ;
    SHAPE ABUTMENT ;
    PORT
      LAYER metal2 ;
      RECT 16.495 236.390 16.565 236.600 ;
    END
  END rw0_rd_out[137]
  PIN rw0_rd_out[138]
    DIRECTION OUTPUT ;
    USE SIGNAL ;
    SHAPE ABUTMENT ;
    PORT
      LAYER metal2 ;
      RECT 18.205 236.390 18.275 236.600 ;
    END
  END rw0_rd_out[138]
  PIN rw0_rd_out[139]
    DIRECTION OUTPUT ;
    USE SIGNAL ;
    SHAPE ABUTMENT ;
    PORT
      LAYER metal2 ;
      RECT 19.915 236.390 19.985 236.600 ;
    END
  END rw0_rd_out[139]
  PIN rw0_rd_out[140]
    DIRECTION OUTPUT ;
    USE SIGNAL ;
    SHAPE ABUTMENT ;
    PORT
      LAYER metal2 ;
      RECT 21.625 236.390 21.695 236.600 ;
    END
  END rw0_rd_out[140]
  PIN rw0_rd_out[141]
    DIRECTION OUTPUT ;
    USE SIGNAL ;
    SHAPE ABUTMENT ;
    PORT
      LAYER metal2 ;
      RECT 23.335 236.390 23.405 236.600 ;
    END
  END rw0_rd_out[141]
  PIN rw0_rd_out[142]
    DIRECTION OUTPUT ;
    USE SIGNAL ;
    SHAPE ABUTMENT ;
    PORT
      LAYER metal2 ;
      RECT 25.045 236.390 25.115 236.600 ;
    END
  END rw0_rd_out[142]
  PIN rw0_rd_out[143]
    DIRECTION OUTPUT ;
    USE SIGNAL ;
    SHAPE ABUTMENT ;
    PORT
      LAYER metal2 ;
      RECT 26.755 236.390 26.825 236.600 ;
    END
  END rw0_rd_out[143]
  PIN rw0_rd_out[144]
    DIRECTION OUTPUT ;
    USE SIGNAL ;
    SHAPE ABUTMENT ;
    PORT
      LAYER metal2 ;
      RECT 28.465 236.390 28.535 236.600 ;
    END
  END rw0_rd_out[144]
  PIN rw0_rd_out[145]
    DIRECTION OUTPUT ;
    USE SIGNAL ;
    SHAPE ABUTMENT ;
    PORT
      LAYER metal2 ;
      RECT 30.175 236.390 30.245 236.600 ;
    END
  END rw0_rd_out[145]
  PIN rw0_rd_out[146]
    DIRECTION OUTPUT ;
    USE SIGNAL ;
    SHAPE ABUTMENT ;
    PORT
      LAYER metal2 ;
      RECT 31.885 236.390 31.955 236.600 ;
    END
  END rw0_rd_out[146]
  PIN rw0_rd_out[147]
    DIRECTION OUTPUT ;
    USE SIGNAL ;
    SHAPE ABUTMENT ;
    PORT
      LAYER metal2 ;
      RECT 33.595 236.390 33.665 236.600 ;
    END
  END rw0_rd_out[147]
  PIN rw0_rd_out[148]
    DIRECTION OUTPUT ;
    USE SIGNAL ;
    SHAPE ABUTMENT ;
    PORT
      LAYER metal2 ;
      RECT 35.305 236.390 35.375 236.600 ;
    END
  END rw0_rd_out[148]
  PIN rw0_rd_out[149]
    DIRECTION OUTPUT ;
    USE SIGNAL ;
    SHAPE ABUTMENT ;
    PORT
      LAYER metal2 ;
      RECT 37.015 236.390 37.085 236.600 ;
    END
  END rw0_rd_out[149]
  PIN rw0_rd_out[150]
    DIRECTION OUTPUT ;
    USE SIGNAL ;
    SHAPE ABUTMENT ;
    PORT
      LAYER metal2 ;
      RECT 38.725 236.390 38.795 236.600 ;
    END
  END rw0_rd_out[150]
  PIN rw0_rd_out[151]
    DIRECTION OUTPUT ;
    USE SIGNAL ;
    SHAPE ABUTMENT ;
    PORT
      LAYER metal2 ;
      RECT 40.435 236.390 40.505 236.600 ;
    END
  END rw0_rd_out[151]
  PIN rw0_rd_out[152]
    DIRECTION OUTPUT ;
    USE SIGNAL ;
    SHAPE ABUTMENT ;
    PORT
      LAYER metal2 ;
      RECT 42.145 236.390 42.215 236.600 ;
    END
  END rw0_rd_out[152]
  PIN rw0_rd_out[153]
    DIRECTION OUTPUT ;
    USE SIGNAL ;
    SHAPE ABUTMENT ;
    PORT
      LAYER metal2 ;
      RECT 43.855 236.390 43.925 236.600 ;
    END
  END rw0_rd_out[153]
  PIN rw0_rd_out[154]
    DIRECTION OUTPUT ;
    USE SIGNAL ;
    SHAPE ABUTMENT ;
    PORT
      LAYER metal2 ;
      RECT 45.565 236.390 45.635 236.600 ;
    END
  END rw0_rd_out[154]
  PIN rw0_rd_out[155]
    DIRECTION OUTPUT ;
    USE SIGNAL ;
    SHAPE ABUTMENT ;
    PORT
      LAYER metal2 ;
      RECT 47.275 236.390 47.345 236.600 ;
    END
  END rw0_rd_out[155]
  PIN rw0_rd_out[156]
    DIRECTION OUTPUT ;
    USE SIGNAL ;
    SHAPE ABUTMENT ;
    PORT
      LAYER metal2 ;
      RECT 48.985 236.390 49.055 236.600 ;
    END
  END rw0_rd_out[156]
  PIN rw0_rd_out[157]
    DIRECTION OUTPUT ;
    USE SIGNAL ;
    SHAPE ABUTMENT ;
    PORT
      LAYER metal2 ;
      RECT 50.695 236.390 50.765 236.600 ;
    END
  END rw0_rd_out[157]
  PIN rw0_rd_out[158]
    DIRECTION OUTPUT ;
    USE SIGNAL ;
    SHAPE ABUTMENT ;
    PORT
      LAYER metal2 ;
      RECT 52.405 236.390 52.475 236.600 ;
    END
  END rw0_rd_out[158]
  PIN rw0_rd_out[159]
    DIRECTION OUTPUT ;
    USE SIGNAL ;
    SHAPE ABUTMENT ;
    PORT
      LAYER metal2 ;
      RECT 54.115 236.390 54.185 236.600 ;
    END
  END rw0_rd_out[159]
  PIN rw0_rd_out[160]
    DIRECTION OUTPUT ;
    USE SIGNAL ;
    SHAPE ABUTMENT ;
    PORT
      LAYER metal2 ;
      RECT 55.825 236.390 55.895 236.600 ;
    END
  END rw0_rd_out[160]
  PIN rw0_rd_out[161]
    DIRECTION OUTPUT ;
    USE SIGNAL ;
    SHAPE ABUTMENT ;
    PORT
      LAYER metal2 ;
      RECT 57.535 236.390 57.605 236.600 ;
    END
  END rw0_rd_out[161]
  PIN rw0_rd_out[162]
    DIRECTION OUTPUT ;
    USE SIGNAL ;
    SHAPE ABUTMENT ;
    PORT
      LAYER metal2 ;
      RECT 59.245 236.390 59.315 236.600 ;
    END
  END rw0_rd_out[162]
  PIN rw0_rd_out[163]
    DIRECTION OUTPUT ;
    USE SIGNAL ;
    SHAPE ABUTMENT ;
    PORT
      LAYER metal2 ;
      RECT 60.955 236.390 61.025 236.600 ;
    END
  END rw0_rd_out[163]
  PIN rw0_rd_out[164]
    DIRECTION OUTPUT ;
    USE SIGNAL ;
    SHAPE ABUTMENT ;
    PORT
      LAYER metal2 ;
      RECT 62.665 236.390 62.735 236.600 ;
    END
  END rw0_rd_out[164]
  PIN rw0_rd_out[165]
    DIRECTION OUTPUT ;
    USE SIGNAL ;
    SHAPE ABUTMENT ;
    PORT
      LAYER metal2 ;
      RECT 64.375 236.390 64.445 236.600 ;
    END
  END rw0_rd_out[165]
  PIN rw0_rd_out[166]
    DIRECTION OUTPUT ;
    USE SIGNAL ;
    SHAPE ABUTMENT ;
    PORT
      LAYER metal2 ;
      RECT 66.085 236.390 66.155 236.600 ;
    END
  END rw0_rd_out[166]
  PIN rw0_rd_out[167]
    DIRECTION OUTPUT ;
    USE SIGNAL ;
    SHAPE ABUTMENT ;
    PORT
      LAYER metal2 ;
      RECT 67.795 236.390 67.865 236.600 ;
    END
  END rw0_rd_out[167]
  PIN rw0_rd_out[168]
    DIRECTION OUTPUT ;
    USE SIGNAL ;
    SHAPE ABUTMENT ;
    PORT
      LAYER metal2 ;
      RECT 69.505 236.390 69.575 236.600 ;
    END
  END rw0_rd_out[168]
  PIN rw0_rd_out[169]
    DIRECTION OUTPUT ;
    USE SIGNAL ;
    SHAPE ABUTMENT ;
    PORT
      LAYER metal2 ;
      RECT 71.215 236.390 71.285 236.600 ;
    END
  END rw0_rd_out[169]
  PIN rw0_rd_out[170]
    DIRECTION OUTPUT ;
    USE SIGNAL ;
    SHAPE ABUTMENT ;
    PORT
      LAYER metal2 ;
      RECT 72.925 236.390 72.995 236.600 ;
    END
  END rw0_rd_out[170]
  PIN rw0_rd_out[171]
    DIRECTION OUTPUT ;
    USE SIGNAL ;
    SHAPE ABUTMENT ;
    PORT
      LAYER metal2 ;
      RECT 74.635 236.390 74.705 236.600 ;
    END
  END rw0_rd_out[171]
  PIN rw0_rd_out[172]
    DIRECTION OUTPUT ;
    USE SIGNAL ;
    SHAPE ABUTMENT ;
    PORT
      LAYER metal2 ;
      RECT 76.345 236.390 76.415 236.600 ;
    END
  END rw0_rd_out[172]
  PIN rw0_rd_out[173]
    DIRECTION OUTPUT ;
    USE SIGNAL ;
    SHAPE ABUTMENT ;
    PORT
      LAYER metal2 ;
      RECT 78.055 236.390 78.125 236.600 ;
    END
  END rw0_rd_out[173]
  PIN rw0_rd_out[174]
    DIRECTION OUTPUT ;
    USE SIGNAL ;
    SHAPE ABUTMENT ;
    PORT
      LAYER metal2 ;
      RECT 79.765 236.390 79.835 236.600 ;
    END
  END rw0_rd_out[174]
  PIN rw0_rd_out[175]
    DIRECTION OUTPUT ;
    USE SIGNAL ;
    SHAPE ABUTMENT ;
    PORT
      LAYER metal2 ;
      RECT 81.475 236.390 81.545 236.600 ;
    END
  END rw0_rd_out[175]
  PIN rw0_rd_out[176]
    DIRECTION OUTPUT ;
    USE SIGNAL ;
    SHAPE ABUTMENT ;
    PORT
      LAYER metal2 ;
      RECT 83.185 236.390 83.255 236.600 ;
    END
  END rw0_rd_out[176]
  PIN rw0_rd_out[177]
    DIRECTION OUTPUT ;
    USE SIGNAL ;
    SHAPE ABUTMENT ;
    PORT
      LAYER metal2 ;
      RECT 84.895 236.390 84.965 236.600 ;
    END
  END rw0_rd_out[177]
  PIN rw0_rd_out[178]
    DIRECTION OUTPUT ;
    USE SIGNAL ;
    SHAPE ABUTMENT ;
    PORT
      LAYER metal2 ;
      RECT 86.605 236.390 86.675 236.600 ;
    END
  END rw0_rd_out[178]
  PIN rw0_rd_out[179]
    DIRECTION OUTPUT ;
    USE SIGNAL ;
    SHAPE ABUTMENT ;
    PORT
      LAYER metal2 ;
      RECT 88.315 236.390 88.385 236.600 ;
    END
  END rw0_rd_out[179]
  PIN rw0_rd_out[180]
    DIRECTION OUTPUT ;
    USE SIGNAL ;
    SHAPE ABUTMENT ;
    PORT
      LAYER metal2 ;
      RECT 90.025 236.390 90.095 236.600 ;
    END
  END rw0_rd_out[180]
  PIN rw0_rd_out[181]
    DIRECTION OUTPUT ;
    USE SIGNAL ;
    SHAPE ABUTMENT ;
    PORT
      LAYER metal2 ;
      RECT 91.735 236.390 91.805 236.600 ;
    END
  END rw0_rd_out[181]
  PIN rw0_rd_out[182]
    DIRECTION OUTPUT ;
    USE SIGNAL ;
    SHAPE ABUTMENT ;
    PORT
      LAYER metal2 ;
      RECT 93.445 236.390 93.515 236.600 ;
    END
  END rw0_rd_out[182]
  PIN rw0_rd_out[183]
    DIRECTION OUTPUT ;
    USE SIGNAL ;
    SHAPE ABUTMENT ;
    PORT
      LAYER metal2 ;
      RECT 95.155 236.390 95.225 236.600 ;
    END
  END rw0_rd_out[183]
  PIN rw0_rd_out[184]
    DIRECTION OUTPUT ;
    USE SIGNAL ;
    SHAPE ABUTMENT ;
    PORT
      LAYER metal2 ;
      RECT 96.865 236.390 96.935 236.600 ;
    END
  END rw0_rd_out[184]
  PIN rw0_rd_out[185]
    DIRECTION OUTPUT ;
    USE SIGNAL ;
    SHAPE ABUTMENT ;
    PORT
      LAYER metal2 ;
      RECT 98.575 236.390 98.645 236.600 ;
    END
  END rw0_rd_out[185]
  PIN rw0_rd_out[186]
    DIRECTION OUTPUT ;
    USE SIGNAL ;
    SHAPE ABUTMENT ;
    PORT
      LAYER metal2 ;
      RECT 100.285 236.390 100.355 236.600 ;
    END
  END rw0_rd_out[186]
  PIN rw0_rd_out[187]
    DIRECTION OUTPUT ;
    USE SIGNAL ;
    SHAPE ABUTMENT ;
    PORT
      LAYER metal2 ;
      RECT 101.995 236.390 102.065 236.600 ;
    END
  END rw0_rd_out[187]
  PIN rw0_rd_out[188]
    DIRECTION OUTPUT ;
    USE SIGNAL ;
    SHAPE ABUTMENT ;
    PORT
      LAYER metal2 ;
      RECT 103.705 236.390 103.775 236.600 ;
    END
  END rw0_rd_out[188]
  PIN rw0_rd_out[189]
    DIRECTION OUTPUT ;
    USE SIGNAL ;
    SHAPE ABUTMENT ;
    PORT
      LAYER metal2 ;
      RECT 105.415 236.390 105.485 236.600 ;
    END
  END rw0_rd_out[189]
  PIN rw0_rd_out[190]
    DIRECTION OUTPUT ;
    USE SIGNAL ;
    SHAPE ABUTMENT ;
    PORT
      LAYER metal2 ;
      RECT 107.125 236.390 107.195 236.600 ;
    END
  END rw0_rd_out[190]
  PIN rw0_rd_out[191]
    DIRECTION OUTPUT ;
    USE SIGNAL ;
    SHAPE ABUTMENT ;
    PORT
      LAYER metal2 ;
      RECT 108.835 236.390 108.905 236.600 ;
    END
  END rw0_rd_out[191]
  PIN rw0_rd_out[192]
    DIRECTION OUTPUT ;
    USE SIGNAL ;
    SHAPE ABUTMENT ;
    PORT
      LAYER metal2 ;
      RECT 110.545 236.390 110.615 236.600 ;
    END
  END rw0_rd_out[192]
  PIN rw0_rd_out[193]
    DIRECTION OUTPUT ;
    USE SIGNAL ;
    SHAPE ABUTMENT ;
    PORT
      LAYER metal2 ;
      RECT 112.255 236.390 112.325 236.600 ;
    END
  END rw0_rd_out[193]
  PIN rw0_rd_out[194]
    DIRECTION OUTPUT ;
    USE SIGNAL ;
    SHAPE ABUTMENT ;
    PORT
      LAYER metal2 ;
      RECT 113.965 236.390 114.035 236.600 ;
    END
  END rw0_rd_out[194]
  PIN rw0_rd_out[195]
    DIRECTION OUTPUT ;
    USE SIGNAL ;
    SHAPE ABUTMENT ;
    PORT
      LAYER metal2 ;
      RECT 115.675 236.390 115.745 236.600 ;
    END
  END rw0_rd_out[195]
  PIN rw0_rd_out[196]
    DIRECTION OUTPUT ;
    USE SIGNAL ;
    SHAPE ABUTMENT ;
    PORT
      LAYER metal2 ;
      RECT 117.385 236.390 117.455 236.600 ;
    END
  END rw0_rd_out[196]
  PIN rw0_rd_out[197]
    DIRECTION OUTPUT ;
    USE SIGNAL ;
    SHAPE ABUTMENT ;
    PORT
      LAYER metal2 ;
      RECT 119.095 236.390 119.165 236.600 ;
    END
  END rw0_rd_out[197]
  PIN rw0_rd_out[198]
    DIRECTION OUTPUT ;
    USE SIGNAL ;
    SHAPE ABUTMENT ;
    PORT
      LAYER metal2 ;
      RECT 120.805 236.390 120.875 236.600 ;
    END
  END rw0_rd_out[198]
  PIN rw0_rd_out[199]
    DIRECTION OUTPUT ;
    USE SIGNAL ;
    SHAPE ABUTMENT ;
    PORT
      LAYER metal2 ;
      RECT 122.515 236.390 122.585 236.600 ;
    END
  END rw0_rd_out[199]
  PIN rw0_rd_out[200]
    DIRECTION OUTPUT ;
    USE SIGNAL ;
    SHAPE ABUTMENT ;
    PORT
      LAYER metal2 ;
      RECT 124.225 236.390 124.295 236.600 ;
    END
  END rw0_rd_out[200]
  PIN rw0_rd_out[201]
    DIRECTION OUTPUT ;
    USE SIGNAL ;
    SHAPE ABUTMENT ;
    PORT
      LAYER metal2 ;
      RECT 125.935 236.390 126.005 236.600 ;
    END
  END rw0_rd_out[201]
  PIN rw0_rd_out[202]
    DIRECTION OUTPUT ;
    USE SIGNAL ;
    SHAPE ABUTMENT ;
    PORT
      LAYER metal2 ;
      RECT 127.645 236.390 127.715 236.600 ;
    END
  END rw0_rd_out[202]
  PIN rw0_rd_out[203]
    DIRECTION OUTPUT ;
    USE SIGNAL ;
    SHAPE ABUTMENT ;
    PORT
      LAYER metal2 ;
      RECT 129.355 236.390 129.425 236.600 ;
    END
  END rw0_rd_out[203]
  PIN rw0_rd_out[204]
    DIRECTION OUTPUT ;
    USE SIGNAL ;
    SHAPE ABUTMENT ;
    PORT
      LAYER metal2 ;
      RECT 131.065 236.390 131.135 236.600 ;
    END
  END rw0_rd_out[204]
  PIN rw0_rd_out[205]
    DIRECTION OUTPUT ;
    USE SIGNAL ;
    SHAPE ABUTMENT ;
    PORT
      LAYER metal2 ;
      RECT 132.775 236.390 132.845 236.600 ;
    END
  END rw0_rd_out[205]
  PIN rw0_rd_out[206]
    DIRECTION OUTPUT ;
    USE SIGNAL ;
    SHAPE ABUTMENT ;
    PORT
      LAYER metal2 ;
      RECT 134.485 236.390 134.555 236.600 ;
    END
  END rw0_rd_out[206]
  PIN rw0_rd_out[207]
    DIRECTION OUTPUT ;
    USE SIGNAL ;
    SHAPE ABUTMENT ;
    PORT
      LAYER metal2 ;
      RECT 136.195 236.390 136.265 236.600 ;
    END
  END rw0_rd_out[207]
  PIN rw0_rd_out[208]
    DIRECTION OUTPUT ;
    USE SIGNAL ;
    SHAPE ABUTMENT ;
    PORT
      LAYER metal2 ;
      RECT 137.905 236.390 137.975 236.600 ;
    END
  END rw0_rd_out[208]
  PIN rw0_rd_out[209]
    DIRECTION OUTPUT ;
    USE SIGNAL ;
    SHAPE ABUTMENT ;
    PORT
      LAYER metal2 ;
      RECT 139.615 236.390 139.685 236.600 ;
    END
  END rw0_rd_out[209]
  PIN rw0_rd_out[210]
    DIRECTION OUTPUT ;
    USE SIGNAL ;
    SHAPE ABUTMENT ;
    PORT
      LAYER metal2 ;
      RECT 141.325 236.390 141.395 236.600 ;
    END
  END rw0_rd_out[210]
  PIN rw0_rd_out[211]
    DIRECTION OUTPUT ;
    USE SIGNAL ;
    SHAPE ABUTMENT ;
    PORT
      LAYER metal2 ;
      RECT 143.035 236.390 143.105 236.600 ;
    END
  END rw0_rd_out[211]
  PIN rw0_rd_out[212]
    DIRECTION OUTPUT ;
    USE SIGNAL ;
    SHAPE ABUTMENT ;
    PORT
      LAYER metal2 ;
      RECT 144.745 236.390 144.815 236.600 ;
    END
  END rw0_rd_out[212]
  PIN rw0_rd_out[213]
    DIRECTION OUTPUT ;
    USE SIGNAL ;
    SHAPE ABUTMENT ;
    PORT
      LAYER metal2 ;
      RECT 146.455 236.390 146.525 236.600 ;
    END
  END rw0_rd_out[213]
  PIN rw0_rd_out[214]
    DIRECTION OUTPUT ;
    USE SIGNAL ;
    SHAPE ABUTMENT ;
    PORT
      LAYER metal2 ;
      RECT 148.165 236.390 148.235 236.600 ;
    END
  END rw0_rd_out[214]
  PIN rw0_rd_out[215]
    DIRECTION OUTPUT ;
    USE SIGNAL ;
    SHAPE ABUTMENT ;
    PORT
      LAYER metal2 ;
      RECT 149.875 236.390 149.945 236.600 ;
    END
  END rw0_rd_out[215]
  PIN rw0_rd_out[216]
    DIRECTION OUTPUT ;
    USE SIGNAL ;
    SHAPE ABUTMENT ;
    PORT
      LAYER metal2 ;
      RECT 151.585 236.390 151.655 236.600 ;
    END
  END rw0_rd_out[216]
  PIN rw0_rd_out[217]
    DIRECTION OUTPUT ;
    USE SIGNAL ;
    SHAPE ABUTMENT ;
    PORT
      LAYER metal2 ;
      RECT 153.295 236.390 153.365 236.600 ;
    END
  END rw0_rd_out[217]
  PIN rw0_rd_out[218]
    DIRECTION OUTPUT ;
    USE SIGNAL ;
    SHAPE ABUTMENT ;
    PORT
      LAYER metal2 ;
      RECT 155.005 236.390 155.075 236.600 ;
    END
  END rw0_rd_out[218]
  PIN rw0_rd_out[219]
    DIRECTION OUTPUT ;
    USE SIGNAL ;
    SHAPE ABUTMENT ;
    PORT
      LAYER metal2 ;
      RECT 156.715 236.390 156.785 236.600 ;
    END
  END rw0_rd_out[219]
  PIN rw0_rd_out[220]
    DIRECTION OUTPUT ;
    USE SIGNAL ;
    SHAPE ABUTMENT ;
    PORT
      LAYER metal2 ;
      RECT 158.425 236.390 158.495 236.600 ;
    END
  END rw0_rd_out[220]
  PIN rw0_rd_out[221]
    DIRECTION OUTPUT ;
    USE SIGNAL ;
    SHAPE ABUTMENT ;
    PORT
      LAYER metal2 ;
      RECT 160.135 236.390 160.205 236.600 ;
    END
  END rw0_rd_out[221]
  PIN rw0_rd_out[222]
    DIRECTION OUTPUT ;
    USE SIGNAL ;
    SHAPE ABUTMENT ;
    PORT
      LAYER metal2 ;
      RECT 161.845 236.390 161.915 236.600 ;
    END
  END rw0_rd_out[222]
  PIN rw0_rd_out[223]
    DIRECTION OUTPUT ;
    USE SIGNAL ;
    SHAPE ABUTMENT ;
    PORT
      LAYER metal2 ;
      RECT 163.555 236.390 163.625 236.600 ;
    END
  END rw0_rd_out[223]
  PIN rw0_rd_out[224]
    DIRECTION OUTPUT ;
    USE SIGNAL ;
    SHAPE ABUTMENT ;
    PORT
      LAYER metal2 ;
      RECT 165.265 236.390 165.335 236.600 ;
    END
  END rw0_rd_out[224]
  PIN rw0_rd_out[225]
    DIRECTION OUTPUT ;
    USE SIGNAL ;
    SHAPE ABUTMENT ;
    PORT
      LAYER metal2 ;
      RECT 166.975 236.390 167.045 236.600 ;
    END
  END rw0_rd_out[225]
  PIN rw0_rd_out[226]
    DIRECTION OUTPUT ;
    USE SIGNAL ;
    SHAPE ABUTMENT ;
    PORT
      LAYER metal2 ;
      RECT 168.685 236.390 168.755 236.600 ;
    END
  END rw0_rd_out[226]
  PIN rw0_rd_out[227]
    DIRECTION OUTPUT ;
    USE SIGNAL ;
    SHAPE ABUTMENT ;
    PORT
      LAYER metal2 ;
      RECT 170.395 236.390 170.465 236.600 ;
    END
  END rw0_rd_out[227]
  PIN rw0_rd_out[228]
    DIRECTION OUTPUT ;
    USE SIGNAL ;
    SHAPE ABUTMENT ;
    PORT
      LAYER metal2 ;
      RECT 172.105 236.390 172.175 236.600 ;
    END
  END rw0_rd_out[228]
  PIN rw0_rd_out[229]
    DIRECTION OUTPUT ;
    USE SIGNAL ;
    SHAPE ABUTMENT ;
    PORT
      LAYER metal2 ;
      RECT 173.815 236.390 173.885 236.600 ;
    END
  END rw0_rd_out[229]
  PIN rw0_rd_out[230]
    DIRECTION OUTPUT ;
    USE SIGNAL ;
    SHAPE ABUTMENT ;
    PORT
      LAYER metal2 ;
      RECT 175.525 236.390 175.595 236.600 ;
    END
  END rw0_rd_out[230]
  PIN rw0_rd_out[231]
    DIRECTION OUTPUT ;
    USE SIGNAL ;
    SHAPE ABUTMENT ;
    PORT
      LAYER metal2 ;
      RECT 177.235 236.390 177.305 236.600 ;
    END
  END rw0_rd_out[231]
  PIN rw0_rd_out[232]
    DIRECTION OUTPUT ;
    USE SIGNAL ;
    SHAPE ABUTMENT ;
    PORT
      LAYER metal2 ;
      RECT 178.945 236.390 179.015 236.600 ;
    END
  END rw0_rd_out[232]
  PIN rw0_rd_out[233]
    DIRECTION OUTPUT ;
    USE SIGNAL ;
    SHAPE ABUTMENT ;
    PORT
      LAYER metal2 ;
      RECT 180.655 236.390 180.725 236.600 ;
    END
  END rw0_rd_out[233]
  PIN rw0_rd_out[234]
    DIRECTION OUTPUT ;
    USE SIGNAL ;
    SHAPE ABUTMENT ;
    PORT
      LAYER metal2 ;
      RECT 182.365 236.390 182.435 236.600 ;
    END
  END rw0_rd_out[234]
  PIN rw0_rd_out[235]
    DIRECTION OUTPUT ;
    USE SIGNAL ;
    SHAPE ABUTMENT ;
    PORT
      LAYER metal2 ;
      RECT 184.075 236.390 184.145 236.600 ;
    END
  END rw0_rd_out[235]
  PIN rw0_rd_out[236]
    DIRECTION OUTPUT ;
    USE SIGNAL ;
    SHAPE ABUTMENT ;
    PORT
      LAYER metal2 ;
      RECT 185.785 236.390 185.855 236.600 ;
    END
  END rw0_rd_out[236]
  PIN rw0_rd_out[237]
    DIRECTION OUTPUT ;
    USE SIGNAL ;
    SHAPE ABUTMENT ;
    PORT
      LAYER metal2 ;
      RECT 187.495 236.390 187.565 236.600 ;
    END
  END rw0_rd_out[237]
  PIN rw0_rd_out[238]
    DIRECTION OUTPUT ;
    USE SIGNAL ;
    SHAPE ABUTMENT ;
    PORT
      LAYER metal2 ;
      RECT 189.205 236.390 189.275 236.600 ;
    END
  END rw0_rd_out[238]
  PIN rw0_rd_out[239]
    DIRECTION OUTPUT ;
    USE SIGNAL ;
    SHAPE ABUTMENT ;
    PORT
      LAYER metal2 ;
      RECT 190.915 236.390 190.985 236.600 ;
    END
  END rw0_rd_out[239]
  PIN rw0_rd_out[240]
    DIRECTION OUTPUT ;
    USE SIGNAL ;
    SHAPE ABUTMENT ;
    PORT
      LAYER metal2 ;
      RECT 192.625 236.390 192.695 236.600 ;
    END
  END rw0_rd_out[240]
  PIN rw0_rd_out[241]
    DIRECTION OUTPUT ;
    USE SIGNAL ;
    SHAPE ABUTMENT ;
    PORT
      LAYER metal2 ;
      RECT 194.335 236.390 194.405 236.600 ;
    END
  END rw0_rd_out[241]
  PIN rw0_rd_out[242]
    DIRECTION OUTPUT ;
    USE SIGNAL ;
    SHAPE ABUTMENT ;
    PORT
      LAYER metal2 ;
      RECT 196.045 236.390 196.115 236.600 ;
    END
  END rw0_rd_out[242]
  PIN rw0_rd_out[243]
    DIRECTION OUTPUT ;
    USE SIGNAL ;
    SHAPE ABUTMENT ;
    PORT
      LAYER metal2 ;
      RECT 197.755 236.390 197.825 236.600 ;
    END
  END rw0_rd_out[243]
  PIN rw0_rd_out[244]
    DIRECTION OUTPUT ;
    USE SIGNAL ;
    SHAPE ABUTMENT ;
    PORT
      LAYER metal2 ;
      RECT 199.465 236.390 199.535 236.600 ;
    END
  END rw0_rd_out[244]
  PIN rw0_rd_out[245]
    DIRECTION OUTPUT ;
    USE SIGNAL ;
    SHAPE ABUTMENT ;
    PORT
      LAYER metal2 ;
      RECT 201.175 236.390 201.245 236.600 ;
    END
  END rw0_rd_out[245]
  PIN rw0_rd_out[246]
    DIRECTION OUTPUT ;
    USE SIGNAL ;
    SHAPE ABUTMENT ;
    PORT
      LAYER metal2 ;
      RECT 202.885 236.390 202.955 236.600 ;
    END
  END rw0_rd_out[246]
  PIN rw0_rd_out[247]
    DIRECTION OUTPUT ;
    USE SIGNAL ;
    SHAPE ABUTMENT ;
    PORT
      LAYER metal2 ;
      RECT 204.595 236.390 204.665 236.600 ;
    END
  END rw0_rd_out[247]
  PIN rw0_rd_out[248]
    DIRECTION OUTPUT ;
    USE SIGNAL ;
    SHAPE ABUTMENT ;
    PORT
      LAYER metal2 ;
      RECT 206.305 236.390 206.375 236.600 ;
    END
  END rw0_rd_out[248]
  PIN rw0_rd_out[249]
    DIRECTION OUTPUT ;
    USE SIGNAL ;
    SHAPE ABUTMENT ;
    PORT
      LAYER metal2 ;
      RECT 208.015 236.390 208.085 236.600 ;
    END
  END rw0_rd_out[249]
  PIN rw0_rd_out[250]
    DIRECTION OUTPUT ;
    USE SIGNAL ;
    SHAPE ABUTMENT ;
    PORT
      LAYER metal2 ;
      RECT 209.725 236.390 209.795 236.600 ;
    END
  END rw0_rd_out[250]
  PIN rw0_rd_out[251]
    DIRECTION OUTPUT ;
    USE SIGNAL ;
    SHAPE ABUTMENT ;
    PORT
      LAYER metal2 ;
      RECT 211.435 236.390 211.505 236.600 ;
    END
  END rw0_rd_out[251]
  PIN rw0_rd_out[252]
    DIRECTION OUTPUT ;
    USE SIGNAL ;
    SHAPE ABUTMENT ;
    PORT
      LAYER metal2 ;
      RECT 213.145 236.390 213.215 236.600 ;
    END
  END rw0_rd_out[252]
  PIN rw0_rd_out[253]
    DIRECTION OUTPUT ;
    USE SIGNAL ;
    SHAPE ABUTMENT ;
    PORT
      LAYER metal2 ;
      RECT 214.855 236.390 214.925 236.600 ;
    END
  END rw0_rd_out[253]
  PIN rw0_rd_out[254]
    DIRECTION OUTPUT ;
    USE SIGNAL ;
    SHAPE ABUTMENT ;
    PORT
      LAYER metal2 ;
      RECT 216.565 236.390 216.635 236.600 ;
    END
  END rw0_rd_out[254]
  PIN rw0_rd_out[255]
    DIRECTION OUTPUT ;
    USE SIGNAL ;
    SHAPE ABUTMENT ;
    PORT
      LAYER metal2 ;
      RECT 218.275 236.390 218.345 236.600 ;
    END
  END rw0_rd_out[255]
  PIN rw0_addr_in[0]
    DIRECTION INPUT ;
    USE SIGNAL ;
    SHAPE ABUTMENT ;
    PORT
      LAYER metal3 ;
      RECT 0.000 215.845 0.210 215.915 ;
    END
  END rw0_addr_in[0]
  PIN rw0_addr_in[1]
    DIRECTION INPUT ;
    USE SIGNAL ;
    SHAPE ABUTMENT ;
    PORT
      LAYER metal3 ;
      RECT 0.000 219.205 0.210 219.275 ;
    END
  END rw0_addr_in[1]
  PIN rw0_addr_in[2]
    DIRECTION INPUT ;
    USE SIGNAL ;
    SHAPE ABUTMENT ;
    PORT
      LAYER metal3 ;
      RECT 0.000 222.565 0.210 222.635 ;
    END
  END rw0_addr_in[2]
  PIN rw0_addr_in[3]
    DIRECTION INPUT ;
    USE SIGNAL ;
    SHAPE ABUTMENT ;
    PORT
      LAYER metal3 ;
      RECT 0.000 225.925 0.210 225.995 ;
    END
  END rw0_addr_in[3]
  PIN rw0_addr_in[4]
    DIRECTION INPUT ;
    USE SIGNAL ;
    SHAPE ABUTMENT ;
    PORT
      LAYER metal3 ;
      RECT 237.670 215.845 237.880 215.915 ;
    END
  END rw0_addr_in[4]
  PIN rw0_addr_in[5]
    DIRECTION INPUT ;
    USE SIGNAL ;
    SHAPE ABUTMENT ;
    PORT
      LAYER metal3 ;
      RECT 237.670 219.205 237.880 219.275 ;
    END
  END rw0_addr_in[5]
  PIN rw0_addr_in[6]
    DIRECTION INPUT ;
    USE SIGNAL ;
    SHAPE ABUTMENT ;
    PORT
      LAYER metal3 ;
      RECT 237.670 222.565 237.880 222.635 ;
    END
  END rw0_addr_in[6]
  PIN rw0_addr_in[7]
    DIRECTION INPUT ;
    USE SIGNAL ;
    SHAPE ABUTMENT ;
    PORT
      LAYER metal3 ;
      RECT 237.670 225.925 237.880 225.995 ;
    END
  END rw0_addr_in[7]
  PIN rw0_we_in
    DIRECTION INPUT ;
    USE SIGNAL ;
    SHAPE ABUTMENT ;
    PORT
      LAYER metal2 ;
      RECT 219.985 236.390 220.055 236.600 ;
    END
  END rw0_we_in
  PIN rw0_ce_in
    DIRECTION INPUT ;
    USE SIGNAL ;
    SHAPE ABUTMENT ;
    PORT
      LAYER metal2 ;
      RECT 221.695 236.390 221.765 236.600 ;
    END
  END rw0_ce_in
  PIN rw0_clk
    DIRECTION INPUT ;
    USE SIGNAL ;
    SHAPE ABUTMENT ;
    PORT
      LAYER metal2 ;
      RECT 223.405 236.390 223.475 236.600 ;
    END
  END rw0_clk
  PIN VSS
    DIRECTION INOUT ;
    USE GROUND ;
    PORT
      LAYER metal4 ;
      RECT 1.000 0.840 1.280 235.760 ;
      RECT 3.240 0.840 3.520 235.760 ;
      RECT 5.480 0.840 5.760 235.760 ;
      RECT 7.720 0.840 8.000 235.760 ;
      RECT 9.960 0.840 10.240 235.760 ;
      RECT 12.200 0.840 12.480 235.760 ;
      RECT 14.440 0.840 14.720 235.760 ;
      RECT 16.680 0.840 16.960 235.760 ;
      RECT 18.920 0.840 19.200 235.760 ;
      RECT 21.160 0.840 21.440 235.760 ;
      RECT 23.400 0.840 23.680 235.760 ;
      RECT 25.640 0.840 25.920 235.760 ;
      RECT 27.880 0.840 28.160 235.760 ;
      RECT 30.120 0.840 30.400 235.760 ;
      RECT 32.360 0.840 32.640 235.760 ;
      RECT 34.600 0.840 34.880 235.760 ;
      RECT 36.840 0.840 37.120 235.760 ;
      RECT 39.080 0.840 39.360 235.760 ;
      RECT 41.320 0.840 41.600 235.760 ;
      RECT 43.560 0.840 43.840 235.760 ;
      RECT 45.800 0.840 46.080 235.760 ;
      RECT 48.040 0.840 48.320 235.760 ;
      RECT 50.280 0.840 50.560 235.760 ;
      RECT 52.520 0.840 52.800 235.760 ;
      RECT 54.760 0.840 55.040 235.760 ;
      RECT 57.000 0.840 57.280 235.760 ;
      RECT 59.240 0.840 59.520 235.760 ;
      RECT 61.480 0.840 61.760 235.760 ;
      RECT 63.720 0.840 64.000 235.760 ;
      RECT 65.960 0.840 66.240 235.760 ;
      RECT 68.200 0.840 68.480 235.760 ;
      RECT 70.440 0.840 70.720 235.760 ;
      RECT 72.680 0.840 72.960 235.760 ;
      RECT 74.920 0.840 75.200 235.760 ;
      RECT 77.160 0.840 77.440 235.760 ;
      RECT 79.400 0.840 79.680 235.760 ;
      RECT 81.640 0.840 81.920 235.760 ;
      RECT 83.880 0.840 84.160 235.760 ;
      RECT 86.120 0.840 86.400 235.760 ;
      RECT 88.360 0.840 88.640 235.760 ;
      RECT 90.600 0.840 90.880 235.760 ;
      RECT 92.840 0.840 93.120 235.760 ;
      RECT 95.080 0.840 95.360 235.760 ;
      RECT 97.320 0.840 97.600 235.760 ;
      RECT 99.560 0.840 99.840 235.760 ;
      RECT 101.800 0.840 102.080 235.760 ;
      RECT 104.040 0.840 104.320 235.760 ;
      RECT 106.280 0.840 106.560 235.760 ;
      RECT 108.520 0.840 108.800 235.760 ;
      RECT 110.760 0.840 111.040 235.760 ;
      RECT 113.000 0.840 113.280 235.760 ;
      RECT 115.240 0.840 115.520 235.760 ;
      RECT 117.480 0.840 117.760 235.760 ;
      RECT 119.720 0.840 120.000 235.760 ;
      RECT 121.960 0.840 122.240 235.760 ;
      RECT 124.200 0.840 124.480 235.760 ;
      RECT 126.440 0.840 126.720 235.760 ;
      RECT 128.680 0.840 128.960 235.760 ;
      RECT 130.920 0.840 131.200 235.760 ;
      RECT 133.160 0.840 133.440 235.760 ;
      RECT 135.400 0.840 135.680 235.760 ;
      RECT 137.640 0.840 137.920 235.760 ;
      RECT 139.880 0.840 140.160 235.760 ;
      RECT 142.120 0.840 142.400 235.760 ;
      RECT 144.360 0.840 144.640 235.760 ;
      RECT 146.600 0.840 146.880 235.760 ;
      RECT 148.840 0.840 149.120 235.760 ;
      RECT 151.080 0.840 151.360 235.760 ;
      RECT 153.320 0.840 153.600 235.760 ;
      RECT 155.560 0.840 155.840 235.760 ;
      RECT 157.800 0.840 158.080 235.760 ;
      RECT 160.040 0.840 160.320 235.760 ;
      RECT 162.280 0.840 162.560 235.760 ;
      RECT 164.520 0.840 164.800 235.760 ;
      RECT 166.760 0.840 167.040 235.760 ;
      RECT 169.000 0.840 169.280 235.760 ;
      RECT 171.240 0.840 171.520 235.760 ;
      RECT 173.480 0.840 173.760 235.760 ;
      RECT 175.720 0.840 176.000 235.760 ;
      RECT 177.960 0.840 178.240 235.760 ;
      RECT 180.200 0.840 180.480 235.760 ;
      RECT 182.440 0.840 182.720 235.760 ;
      RECT 184.680 0.840 184.960 235.760 ;
      RECT 186.920 0.840 187.200 235.760 ;
      RECT 189.160 0.840 189.440 235.760 ;
      RECT 191.400 0.840 191.680 235.760 ;
      RECT 193.640 0.840 193.920 235.760 ;
      RECT 195.880 0.840 196.160 235.760 ;
      RECT 198.120 0.840 198.400 235.760 ;
      RECT 200.360 0.840 200.640 235.760 ;
      RECT 202.600 0.840 202.880 235.760 ;
      RECT 204.840 0.840 205.120 235.760 ;
      RECT 207.080 0.840 207.360 235.760 ;
      RECT 209.320 0.840 209.600 235.760 ;
      RECT 211.560 0.840 211.840 235.760 ;
      RECT 213.800 0.840 214.080 235.760 ;
      RECT 216.040 0.840 216.320 235.760 ;
      RECT 218.280 0.840 218.560 235.760 ;
      RECT 220.520 0.840 220.800 235.760 ;
      RECT 222.760 0.840 223.040 235.760 ;
      RECT 225.000 0.840 225.280 235.760 ;
      RECT 227.240 0.840 227.520 235.760 ;
      RECT 229.480 0.840 229.760 235.760 ;
      RECT 231.720 0.840 232.000 235.760 ;
      RECT 233.960 0.840 234.240 235.760 ;
      RECT 236.200 0.840 236.480 235.760 ;
    END
  END VSS
  PIN VDD
    DIRECTION INOUT ;
    USE POWER ;
    PORT
      LAYER metal4 ;
      RECT 2.120 0.840 2.400 235.760 ;
      RECT 4.360 0.840 4.640 235.760 ;
      RECT 6.600 0.840 6.880 235.760 ;
      RECT 8.840 0.840 9.120 235.760 ;
      RECT 11.080 0.840 11.360 235.760 ;
      RECT 13.320 0.840 13.600 235.760 ;
      RECT 15.560 0.840 15.840 235.760 ;
      RECT 17.800 0.840 18.080 235.760 ;
      RECT 20.040 0.840 20.320 235.760 ;
      RECT 22.280 0.840 22.560 235.760 ;
      RECT 24.520 0.840 24.800 235.760 ;
      RECT 26.760 0.840 27.040 235.760 ;
      RECT 29.000 0.840 29.280 235.760 ;
      RECT 31.240 0.840 31.520 235.760 ;
      RECT 33.480 0.840 33.760 235.760 ;
      RECT 35.720 0.840 36.000 235.760 ;
      RECT 37.960 0.840 38.240 235.760 ;
      RECT 40.200 0.840 40.480 235.760 ;
      RECT 42.440 0.840 42.720 235.760 ;
      RECT 44.680 0.840 44.960 235.760 ;
      RECT 46.920 0.840 47.200 235.760 ;
      RECT 49.160 0.840 49.440 235.760 ;
      RECT 51.400 0.840 51.680 235.760 ;
      RECT 53.640 0.840 53.920 235.760 ;
      RECT 55.880 0.840 56.160 235.760 ;
      RECT 58.120 0.840 58.400 235.760 ;
      RECT 60.360 0.840 60.640 235.760 ;
      RECT 62.600 0.840 62.880 235.760 ;
      RECT 64.840 0.840 65.120 235.760 ;
      RECT 67.080 0.840 67.360 235.760 ;
      RECT 69.320 0.840 69.600 235.760 ;
      RECT 71.560 0.840 71.840 235.760 ;
      RECT 73.800 0.840 74.080 235.760 ;
      RECT 76.040 0.840 76.320 235.760 ;
      RECT 78.280 0.840 78.560 235.760 ;
      RECT 80.520 0.840 80.800 235.760 ;
      RECT 82.760 0.840 83.040 235.760 ;
      RECT 85.000 0.840 85.280 235.760 ;
      RECT 87.240 0.840 87.520 235.760 ;
      RECT 89.480 0.840 89.760 235.760 ;
      RECT 91.720 0.840 92.000 235.760 ;
      RECT 93.960 0.840 94.240 235.760 ;
      RECT 96.200 0.840 96.480 235.760 ;
      RECT 98.440 0.840 98.720 235.760 ;
      RECT 100.680 0.840 100.960 235.760 ;
      RECT 102.920 0.840 103.200 235.760 ;
      RECT 105.160 0.840 105.440 235.760 ;
      RECT 107.400 0.840 107.680 235.760 ;
      RECT 109.640 0.840 109.920 235.760 ;
      RECT 111.880 0.840 112.160 235.760 ;
      RECT 114.120 0.840 114.400 235.760 ;
      RECT 116.360 0.840 116.640 235.760 ;
      RECT 118.600 0.840 118.880 235.760 ;
      RECT 120.840 0.840 121.120 235.760 ;
      RECT 123.080 0.840 123.360 235.760 ;
      RECT 125.320 0.840 125.600 235.760 ;
      RECT 127.560 0.840 127.840 235.760 ;
      RECT 129.800 0.840 130.080 235.760 ;
      RECT 132.040 0.840 132.320 235.760 ;
      RECT 134.280 0.840 134.560 235.760 ;
      RECT 136.520 0.840 136.800 235.760 ;
      RECT 138.760 0.840 139.040 235.760 ;
      RECT 141.000 0.840 141.280 235.760 ;
      RECT 143.240 0.840 143.520 235.760 ;
      RECT 145.480 0.840 145.760 235.760 ;
      RECT 147.720 0.840 148.000 235.760 ;
      RECT 149.960 0.840 150.240 235.760 ;
      RECT 152.200 0.840 152.480 235.760 ;
      RECT 154.440 0.840 154.720 235.760 ;
      RECT 156.680 0.840 156.960 235.760 ;
      RECT 158.920 0.840 159.200 235.760 ;
      RECT 161.160 0.840 161.440 235.760 ;
      RECT 163.400 0.840 163.680 235.760 ;
      RECT 165.640 0.840 165.920 235.760 ;
      RECT 167.880 0.840 168.160 235.760 ;
      RECT 170.120 0.840 170.400 235.760 ;
      RECT 172.360 0.840 172.640 235.760 ;
      RECT 174.600 0.840 174.880 235.760 ;
      RECT 176.840 0.840 177.120 235.760 ;
      RECT 179.080 0.840 179.360 235.760 ;
      RECT 181.320 0.840 181.600 235.760 ;
      RECT 183.560 0.840 183.840 235.760 ;
      RECT 185.800 0.840 186.080 235.760 ;
      RECT 188.040 0.840 188.320 235.760 ;
      RECT 190.280 0.840 190.560 235.760 ;
      RECT 192.520 0.840 192.800 235.760 ;
      RECT 194.760 0.840 195.040 235.760 ;
      RECT 197.000 0.840 197.280 235.760 ;
      RECT 199.240 0.840 199.520 235.760 ;
      RECT 201.480 0.840 201.760 235.760 ;
      RECT 203.720 0.840 204.000 235.760 ;
      RECT 205.960 0.840 206.240 235.760 ;
      RECT 208.200 0.840 208.480 235.760 ;
      RECT 210.440 0.840 210.720 235.760 ;
      RECT 212.680 0.840 212.960 235.760 ;
      RECT 214.920 0.840 215.200 235.760 ;
      RECT 217.160 0.840 217.440 235.760 ;
      RECT 219.400 0.840 219.680 235.760 ;
      RECT 221.640 0.840 221.920 235.760 ;
      RECT 223.880 0.840 224.160 235.760 ;
      RECT 226.120 0.840 226.400 235.760 ;
      RECT 228.360 0.840 228.640 235.760 ;
      RECT 230.600 0.840 230.880 235.760 ;
      RECT 232.840 0.840 233.120 235.760 ;
      RECT 235.080 0.840 235.360 235.760 ;
      RECT 237.320 0.840 237.600 235.760 ;
    END
  END VDD
  OBS
    LAYER metal1 ;
    RECT 0 0 237.880 236.600 ;
    LAYER metal2 ;
    RECT 0 0 237.880 236.600 ;
    LAYER metal3 ;
    RECT 0 0 237.880 236.600 ;
    LAYER metal4 ;
    RECT 0 0 237.880 236.600 ;
    LAYER OVERLAP ;
    RECT 0 0 237.880 236.600 ;
  END
END fakeram_256x256

END LIBRARY
